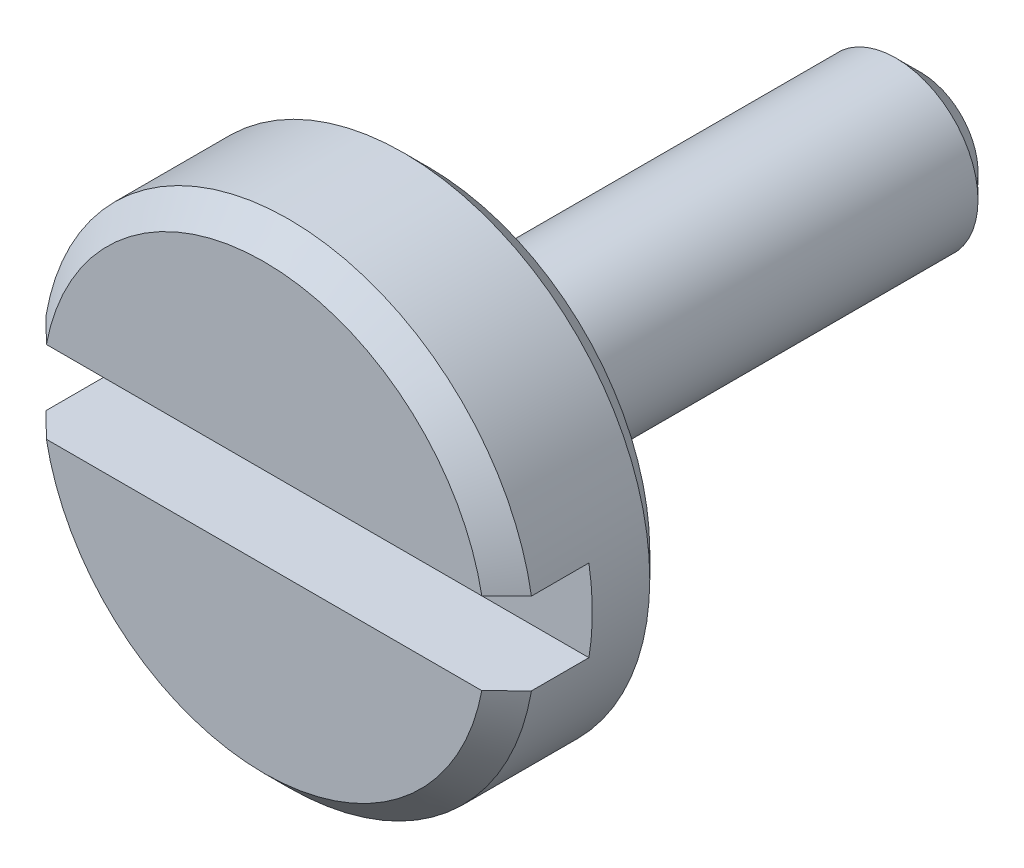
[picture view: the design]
ISO-10303-21;
HEADER;
FILE_DESCRIPTION(('STEP AP214'),'2;1');
FILE_NAME('part.step','',(''),(''),'','','');
FILE_SCHEMA(('AUTOMOTIVE_DESIGN { 1 0 10303 214 1 1 1 1 }'));
ENDSEC;
DATA;
#1=APPLICATION_CONTEXT('core data for automotive mechanical design processes');
#2=APPLICATION_PROTOCOL_DEFINITION('international standard','automotive_design',2000,#1);
#3=PRODUCT_CONTEXT('',#1,'mechanical');
#4=PRODUCT('Part','Part','',(#3));
#5=PRODUCT_RELATED_PRODUCT_CATEGORY('part','',(#4));
#6=PRODUCT_DEFINITION_FORMATION('','',#4);
#7=PRODUCT_DEFINITION_CONTEXT('part definition',#1,'design');
#8=PRODUCT_DEFINITION('design','',#6,#7);
#9=PRODUCT_DEFINITION_SHAPE('','',#8);
#10=(LENGTH_UNIT() NAMED_UNIT(*) SI_UNIT(.MILLI.,.METRE.));
#11=(NAMED_UNIT(*) PLANE_ANGLE_UNIT() SI_UNIT($,.RADIAN.));
#12=(NAMED_UNIT(*) SI_UNIT($,.STERADIAN.) SOLID_ANGLE_UNIT());
#13=UNCERTAINTY_MEASURE_WITH_UNIT(LENGTH_MEASURE(1.E-05),#10,'distance_accuracy_value','');
#14=(GEOMETRIC_REPRESENTATION_CONTEXT(3) GLOBAL_UNCERTAINTY_ASSIGNED_CONTEXT((#13)) GLOBAL_UNIT_ASSIGNED_CONTEXT((#10,
#11,#12)) REPRESENTATION_CONTEXT('',''));
#15=CARTESIAN_POINT('',(0.,0.,0.));
#16=DIRECTION('',(0.,0.,1.));
#17=DIRECTION('',(1.,0.,0.));
#18=AXIS2_PLACEMENT_3D('',#15,#16,#17);
#19=CARTESIAN_POINT('',(0.,0.,-60.));
#20=DIRECTION('',(0.,0.,-1.));
#21=DIRECTION('',(-1.,0.,0.));
#22=AXIS2_PLACEMENT_3D('',#19,#20,#21);
#23=PLANE('',#22);
#24=CARTESIAN_POINT('',(0.,0.,-60.));
#25=DIRECTION('',(0.,0.,-1.));
#26=DIRECTION('',(-1.,0.,0.));
#27=AXIS2_PLACEMENT_3D('',#24,#25,#26);
#28=CIRCLE('',#27,7.00000000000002);
#29=CARTESIAN_POINT('',(-7.00000000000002,0.,-60.));
#30=VERTEX_POINT('',#29);
#31=EDGE_CURVE('E345',#30,#30,#28,.T.);
#32=ORIENTED_EDGE('',*,*,#31,.T.);
#33=EDGE_LOOP('',(#32));
#34=FACE_BOUND('',#33,.T.);
#35=CARTESIAN_POINT('',(-0.572517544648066,-0.773288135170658,-60.));
#36=CARTESIAN_POINT('',(-0.571860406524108,-0.804666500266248,-60.));
#37=CARTESIAN_POINT('',(-0.570558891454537,-0.866813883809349,-60.));
#38=CARTESIAN_POINT('',(-0.555597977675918,-0.95806896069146,-60.));
#39=CARTESIAN_POINT('',(-0.533678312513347,-1.04669983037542,-60.));
#40=CARTESIAN_POINT('',(-0.500641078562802,-1.13161094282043,-60.));
#41=CARTESIAN_POINT('',(-0.460317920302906,-1.21435570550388,-60.));
#42=CARTESIAN_POINT('',(-0.409151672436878,-1.2927636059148,-60.));
#43=CARTESIAN_POINT('',(-0.349843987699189,-1.36857000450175,-60.));
#44=CARTESIAN_POINT('',(-0.281810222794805,-1.43975349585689,-60.));
#45=CARTESIAN_POINT('',(-0.207364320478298,-1.5050996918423,-60.));
#46=CARTESIAN_POINT('',(-0.128680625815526,-1.56322875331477,-60.));
#47=CARTESIAN_POINT('',(-0.0456303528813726,-1.61169707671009,-60.));
#48=CARTESIAN_POINT('',(0.0413359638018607,-1.65124791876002,-60.));
#49=CARTESIAN_POINT('',(0.132238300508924,-1.68218143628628,-60.));
#50=CARTESIAN_POINT('',(0.227046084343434,-1.70459430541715,-60.));
#51=CARTESIAN_POINT('',(0.325915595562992,-1.71835001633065,-60.));
#52=CARTESIAN_POINT('',(0.393116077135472,-1.71977777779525,-60.));
#53=CARTESIAN_POINT('',(0.427282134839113,-1.72050368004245,-60.));
#54=B_SPLINE_CURVE_WITH_KNOTS('',3,(#35,#36,#37,#38,#39,#40,#41,#42,#43,#44,#45,#46,#47,#48,#49,
#50,#51,#52,#53),.UNSPECIFIED.,.F.,.F.,(4,1,1,1,1,1,1,1,1,1,1,1,1,1,1,1,4),(0.,
0.0614842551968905,0.12177452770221,0.180919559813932,0.240256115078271,0.300114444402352,
0.361145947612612,0.423500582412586,0.488669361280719,0.553954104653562,0.617581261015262,
0.68023842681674,0.742187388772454,0.804663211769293,0.868258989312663,0.933020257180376,1.),.UNSPECIFIED.);
#55=CARTESIAN_POINT('',(-0.572517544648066,-0.773288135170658,-60.));
#56=VERTEX_POINT('',#55);
#57=CARTESIAN_POINT('',(0.427282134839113,-1.72050368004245,-60.));
#58=VERTEX_POINT('',#57);
#59=EDGE_CURVE('E216',#56,#58,#54,.T.);
#60=ORIENTED_EDGE('',*,*,#59,.T.);
#61=CARTESIAN_POINT('',(0.427282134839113,-1.72050368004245,-60.));
#62=CARTESIAN_POINT('',(0.453717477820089,-1.71999249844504,-60.));
#63=CARTESIAN_POINT('',(0.506255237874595,-1.71897657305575,-60.));
#64=CARTESIAN_POINT('',(0.583964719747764,-1.70999529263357,-60.));
#65=CARTESIAN_POINT('',(0.660104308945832,-1.69728818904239,-60.));
#66=CARTESIAN_POINT('',(0.733718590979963,-1.67711411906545,-60.));
#67=CARTESIAN_POINT('',(0.805756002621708,-1.65263714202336,-60.));
#68=CARTESIAN_POINT('',(0.875903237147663,-1.62249880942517,-60.));
#69=CARTESIAN_POINT('',(0.944194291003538,-1.5863816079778,-60.));
#70=CARTESIAN_POINT('',(1.01101187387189,-1.54508658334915,-60.));
#71=CARTESIAN_POINT('',(1.07618604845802,-1.49702883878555,-60.));
#72=CARTESIAN_POINT('',(1.13910551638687,-1.44105534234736,-60.));
#73=CARTESIAN_POINT('',(1.20183470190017,-1.37870983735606,-60.));
#74=CARTESIAN_POINT('',(1.26252209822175,-1.30829927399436,-60.));
#75=CARTESIAN_POINT('',(1.32239524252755,-1.23096119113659,-60.));
#76=CARTESIAN_POINT('',(1.38027365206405,-1.14597200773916,-60.));
#77=CARTESIAN_POINT('',(1.43735536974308,-1.05379465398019,-60.));
#78=CARTESIAN_POINT('',(1.47317083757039,-0.98892956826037,-60.));
#79=CARTESIAN_POINT('',(1.4915850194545,-0.955579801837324,-60.));
#80=B_SPLINE_CURVE_WITH_KNOTS('',3,(#61,#62,#63,#64,#65,#66,#67,#68,#69,#70,#71,#72,#73,#74,#75,
#76,#77,#78,#79),.UNSPECIFIED.,.F.,.F.,(4,1,1,1,1,1,1,1,1,1,1,1,1,1,1,1,4),(0.,
0.0572082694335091,0.11369605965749,0.169177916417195,0.224159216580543,0.278719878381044,
0.333794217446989,0.389241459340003,0.445822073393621,0.50370428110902,0.564293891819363,
0.627975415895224,0.695038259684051,0.765372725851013,0.839611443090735,0.917537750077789,1.),.UNSPECIFIED.);
#81=CARTESIAN_POINT('',(1.4915850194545,-0.955579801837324,-60.));
#82=VERTEX_POINT('',#81);
#83=EDGE_CURVE('E49',#58,#82,#80,.T.);
#84=ORIENTED_EDGE('',*,*,#83,.T.);
#85=DIRECTION('',(-0.857672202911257,0.514196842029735,0.));
#86=VECTOR('',#85,1.);
#87=CARTESIAN_POINT('',(1.4915850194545,-0.955579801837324,-60.));
#88=LINE('',#87,#86);
#89=CARTESIAN_POINT('',(1.1957116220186,-0.77819598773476,-60.));
#90=VERTEX_POINT('',#89);
#91=EDGE_CURVE('E220',#82,#90,#88,.T.);
#92=ORIENTED_EDGE('',*,*,#91,.T.);
#93=CARTESIAN_POINT('',(1.1957116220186,-0.77819598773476,-60.));
#94=CARTESIAN_POINT('',(1.16819338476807,-0.824260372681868,-60.));
#95=CARTESIAN_POINT('',(1.11546950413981,-0.912517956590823,-60.));
#96=CARTESIAN_POINT('',(1.02751814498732,-1.0317759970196,-60.));
#97=CARTESIAN_POINT('',(0.9363852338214,-1.13313815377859,-60.));
#98=CARTESIAN_POINT('',(0.841395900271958,-1.21601476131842,-60.));
#99=CARTESIAN_POINT('',(0.743129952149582,-1.28126364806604,-60.));
#100=CARTESIAN_POINT('',(0.640945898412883,-1.32746587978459,-60.));
#101=CARTESIAN_POINT('',(0.535188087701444,-1.35628185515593,-60.));
#102=CARTESIAN_POINT('',(0.463214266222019,-1.35978194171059,-60.));
#103=CARTESIAN_POINT('',(0.427282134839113,-1.36152932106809,-60.));
#104=B_SPLINE_CURVE_WITH_KNOTS('',3,(#93,#94,#95,#96,#97,#98,#99,#100,#101,#102,#103),
.UNSPECIFIED.,.F.,.F.,(4,1,1,1,1,1,1,1,4),(0.,0.159004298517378,0.304646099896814,
0.438546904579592,0.562322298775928,0.677432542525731,0.786897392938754,0.893610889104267,1.),.UNSPECIFIED.);
#105=CARTESIAN_POINT('',(0.427282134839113,-1.36152932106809,-60.));
#106=VERTEX_POINT('',#105);
#107=EDGE_CURVE('E673',#90,#106,#104,.T.);
#108=ORIENTED_EDGE('',*,*,#107,.T.);
#109=CARTESIAN_POINT('',(0.427282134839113,-1.36152932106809,-60.));
#110=CARTESIAN_POINT('',(0.39659527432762,-1.36067464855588,-60.));
#111=CARTESIAN_POINT('',(0.335758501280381,-1.35898025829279,-60.));
#112=CARTESIAN_POINT('',(0.246196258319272,-1.34269945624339,-60.));
#113=CARTESIAN_POINT('',(0.159214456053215,-1.31768732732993,-60.));
#114=CARTESIAN_POINT('',(0.0766058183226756,-1.28186639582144,-60.));
#115=CARTESIAN_POINT('',(-0.000489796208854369,-1.23852791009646,-60.));
#116=CARTESIAN_POINT('',(-0.0680964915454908,-1.18618173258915,-60.));
#117=CARTESIAN_POINT('',(-0.126542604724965,-1.12757552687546,-60.));
#118=CARTESIAN_POINT('',(-0.174351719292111,-1.06219287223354,-60.));
#119=CARTESIAN_POINT('',(-0.211031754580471,-0.991875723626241,-60.));
#120=CARTESIAN_POINT('',(-0.239223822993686,-0.919699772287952,-60.));
#121=CARTESIAN_POINT('',(-0.25486889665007,-0.844531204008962,-60.));
#122=CARTESIAN_POINT('',(-0.257225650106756,-0.793920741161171,-60.));
#123=CARTESIAN_POINT('',(-0.258414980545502,-0.768380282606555,-60.));
#124=B_SPLINE_CURVE_WITH_KNOTS('',3,(#109,#110,#111,#112,#113,#114,#115,#116,#117,#118,#119,
#120,#121,#122,#123),.UNSPECIFIED.,.F.,.F.,(4,1,1,1,1,1,1,1,1,1,1,1,4),(0.,0.0912636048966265,
0.180930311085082,0.270088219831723,0.360156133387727,0.448342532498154,0.53266584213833,
0.613833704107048,0.693981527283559,0.772715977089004,0.849335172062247,0.923967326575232,1.),.UNSPECIFIED.);
#125=CARTESIAN_POINT('',(-0.258414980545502,-0.768380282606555,-60.));
#126=VERTEX_POINT('',#125);
#127=EDGE_CURVE('E678',#106,#126,#124,.T.);
#128=ORIENTED_EDGE('',*,*,#127,.T.);
#129=CARTESIAN_POINT('',(-0.258414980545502,-0.768380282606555,-60.));
#130=CARTESIAN_POINT('',(-0.256940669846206,-0.739239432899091,-60.));
#131=CARTESIAN_POINT('',(-0.253943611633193,-0.680000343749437,-60.));
#132=CARTESIAN_POINT('',(-0.228612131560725,-0.592600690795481,-60.));
#133=CARTESIAN_POINT('',(-0.188762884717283,-0.506108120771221,-60.));
#134=CARTESIAN_POINT('',(-0.152000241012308,-0.45260685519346,-60.));
#135=CARTESIAN_POINT('',(-0.132914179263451,-0.424830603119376,-60.));
#136=B_SPLINE_CURVE_WITH_KNOTS('',3,(#129,#130,#131,#132,#133,#134,#135),.UNSPECIFIED.,.F.,.F.,
(4,1,1,1,4),(0.,0.234723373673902,0.477158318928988,0.728556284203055,1.),.UNSPECIFIED.);
#137=CARTESIAN_POINT('',(-0.132914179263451,-0.424830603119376,-60.));
#138=VERTEX_POINT('',#137);
#139=EDGE_CURVE('E686',#126,#138,#136,.T.);
#140=ORIENTED_EDGE('',*,*,#139,.T.);
#141=CARTESIAN_POINT('',(-0.132914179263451,-0.424830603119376,-60.));
#142=CARTESIAN_POINT('',(-0.117243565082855,-0.404783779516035,-60.));
#143=CARTESIAN_POINT('',(-0.0843450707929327,-0.36269798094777,-60.));
#144=CARTESIAN_POINT('',(-0.0277875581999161,-0.300052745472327,-60.));
#145=CARTESIAN_POINT('',(0.0385785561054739,-0.235434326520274,-60.));
#146=CARTESIAN_POINT('',(0.112482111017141,-0.166375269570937,-60.));
#147=CARTESIAN_POINT('',(0.196615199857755,-0.0960874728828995,-60.));
#148=CARTESIAN_POINT('',(0.288342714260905,-0.0212191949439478,-60.));
#149=CARTESIAN_POINT('',(0.390006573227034,0.0553823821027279,-60.));
#150=CARTESIAN_POINT('',(0.461306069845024,0.106754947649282,-60.));
#151=CARTESIAN_POINT('',(0.498095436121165,0.133262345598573,-60.));
#152=B_SPLINE_CURVE_WITH_KNOTS('',3,(#141,#142,#143,#144,#145,#146,#147,#148,#149,#150,#151),
.UNSPECIFIED.,.F.,.F.,(4,1,1,1,1,1,1,1,4),(0.,0.0902792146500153,0.189529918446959,
0.299197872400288,0.418925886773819,0.548376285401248,0.688136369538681,0.83908350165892,1.),.UNSPECIFIED.);
#153=CARTESIAN_POINT('',(0.498095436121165,0.133262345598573,-60.));
#154=VERTEX_POINT('',#153);
#155=EDGE_CURVE('E694',#138,#154,#152,.T.);
#156=ORIENTED_EDGE('',*,*,#155,.T.);
#157=CARTESIAN_POINT('',(0.498095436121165,0.133262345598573,-60.));
#158=CARTESIAN_POINT('',(0.534919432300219,0.1594909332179,-60.));
#159=CARTESIAN_POINT('',(0.605324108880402,0.209637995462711,-60.));
#160=CARTESIAN_POINT('',(0.703782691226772,0.284062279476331,-60.));
#161=CARTESIAN_POINT('',(0.791827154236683,0.352106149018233,-60.));
#162=CARTESIAN_POINT('',(0.869066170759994,0.414410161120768,-60.));
#163=CARTESIAN_POINT('',(0.935465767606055,0.470982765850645,-60.));
#164=CARTESIAN_POINT('',(0.9915491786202,0.521280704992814,-60.));
#165=CARTESIAN_POINT('',(1.03588773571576,0.566664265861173,-60.));
#166=CARTESIAN_POINT('',(1.06054331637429,0.596105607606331,-60.));
#167=CARTESIAN_POINT('',(1.07161306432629,0.609324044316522,-60.));
#168=B_SPLINE_CURVE_WITH_KNOTS('',3,(#157,#158,#159,#160,#161,#162,#163,#164,#165,#166,#167),
.UNSPECIFIED.,.F.,.F.,(4,1,1,1,1,1,1,1,4),(0.,0.181535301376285,0.347081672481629,
0.495567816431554,0.628357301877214,0.745519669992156,0.845830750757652,0.930781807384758,1.),.UNSPECIFIED.);
#169=CARTESIAN_POINT('',(1.07161306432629,0.609324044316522,-60.));
#170=VERTEX_POINT('',#169);
#171=EDGE_CURVE('E702',#154,#170,#168,.T.);
#172=ORIENTED_EDGE('',*,*,#171,.T.);
#173=CARTESIAN_POINT('',(1.07161306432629,0.609324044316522,-60.));
#174=CARTESIAN_POINT('',(1.08708560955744,0.629925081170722,-60.));
#175=CARTESIAN_POINT('',(1.11751444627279,0.670439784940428,-60.));
#176=CARTESIAN_POINT('',(1.15768045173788,0.733764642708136,-60.));
#177=CARTESIAN_POINT('',(1.19181961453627,0.798587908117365,-60.));
#178=CARTESIAN_POINT('',(1.21858194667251,0.865083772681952,-60.));
#179=CARTESIAN_POINT('',(1.24111816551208,0.932318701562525,-60.));
#180=CARTESIAN_POINT('',(1.25627609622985,1.00116994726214,-60.));
#181=CARTESIAN_POINT('',(1.26576749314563,1.07132856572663,-60.));
#182=CARTESIAN_POINT('',(1.26673947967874,1.11854206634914,-60.));
#183=CARTESIAN_POINT('',(1.26722604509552,1.14217660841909,-60.));
#184=B_SPLINE_CURVE_WITH_KNOTS('',3,(#173,#174,#175,#176,#177,#178,#179,#180,#181,#182,#183),
.UNSPECIFIED.,.F.,.F.,(4,1,1,1,1,1,1,1,4),(0.,0.133506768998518,0.26255897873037,
0.388264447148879,0.512667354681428,0.63372226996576,0.755393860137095,0.877552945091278,1.),.UNSPECIFIED.);
#185=CARTESIAN_POINT('',(1.26722604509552,1.14217660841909,-60.));
#186=VERTEX_POINT('',#185);
#187=EDGE_CURVE('E710',#170,#186,#184,.T.);
#188=ORIENTED_EDGE('',*,*,#187,.T.);
#189=CARTESIAN_POINT('',(1.26722604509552,1.14217660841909,-60.));
#190=CARTESIAN_POINT('',(1.26592083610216,1.17920638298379,-60.));
#191=CARTESIAN_POINT('',(1.26333831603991,1.25247444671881,-60.));
#192=CARTESIAN_POINT('',(1.2414977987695,1.35950527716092,-60.));
#193=CARTESIAN_POINT('',(1.20702490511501,1.46169169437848,-60.));
#194=CARTESIAN_POINT('',(1.15873001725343,1.5580220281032,-60.));
#195=CARTESIAN_POINT('',(1.0964726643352,1.64598800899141,-60.));
#196=CARTESIAN_POINT('',(1.02442668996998,1.72660149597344,-60.));
#197=CARTESIAN_POINT('',(0.938615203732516,1.79437007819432,-60.));
#198=CARTESIAN_POINT('',(0.844462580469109,1.85358213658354,-60.));
#199=CARTESIAN_POINT('',(0.741406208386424,1.89992806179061,-60.));
#200=CARTESIAN_POINT('',(0.633415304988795,1.9348890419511,-60.));
#201=CARTESIAN_POINT('',(0.520318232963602,1.95469829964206,-60.));
#202=CARTESIAN_POINT('',(0.443715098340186,1.9575410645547,-60.));
#203=CARTESIAN_POINT('',(0.404846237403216,1.95898349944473,-60.));
#204=B_SPLINE_CURVE_WITH_KNOTS('',3,(#189,#190,#191,#192,#193,#194,#195,#196,#197,#198,#199,
#200,#201,#202,#203),.UNSPECIFIED.,.F.,.F.,(4,1,1,1,1,1,1,1,1,1,1,1,4),(0.,0.0837853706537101,
0.165779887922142,0.246280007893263,0.32746092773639,0.408796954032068,0.489715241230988,
0.571376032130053,0.655523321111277,0.741019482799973,0.826546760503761,0.911988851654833,1.),.UNSPECIFIED.);
#205=CARTESIAN_POINT('',(0.404846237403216,1.95898349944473,-60.));
#206=VERTEX_POINT('',#205);
#207=EDGE_CURVE('E718',#186,#206,#204,.T.);
#208=ORIENTED_EDGE('',*,*,#207,.T.);
#209=CARTESIAN_POINT('',(0.404846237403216,1.95898349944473,-60.));
#210=CARTESIAN_POINT('',(0.363602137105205,1.95756094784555,-60.));
#211=CARTESIAN_POINT('',(0.281580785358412,1.95473194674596,-60.));
#212=CARTESIAN_POINT('',(0.160931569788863,1.93013441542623,-60.));
#213=CARTESIAN_POINT('',(0.0447708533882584,1.88943374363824,-60.));
#214=CARTESIAN_POINT('',(-0.048672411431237,1.84324508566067,-60.));
#215=CARTESIAN_POINT('',(-0.121805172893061,1.7971136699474,-60.));
#216=CARTESIAN_POINT('',(-0.177577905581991,1.75509384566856,-60.));
#217=CARTESIAN_POINT('',(-0.234095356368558,1.70671873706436,-60.));
#218=CARTESIAN_POINT('',(-0.291813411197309,1.65185949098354,-60.));
#219=CARTESIAN_POINT('',(-0.349754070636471,1.59001273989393,-60.));
#220=CARTESIAN_POINT('',(-0.408777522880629,1.52160205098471,-60.));
#221=CARTESIAN_POINT('',(-0.46902179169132,1.44704549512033,-60.));
#222=CARTESIAN_POINT('',(-0.507777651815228,1.39382099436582,-60.));
#223=CARTESIAN_POINT('',(-0.527645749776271,1.36653558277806,-60.));
#224=B_SPLINE_CURVE_WITH_KNOTS('',3,(#209,#210,#211,#212,#213,#214,#215,#216,#217,#218,#219,
#220,#221,#222,#223),.UNSPECIFIED.,.F.,.F.,(4,1,1,1,1,1,1,1,1,1,1,1,4),(0.,0.107232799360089,
0.213251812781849,0.318830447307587,0.426793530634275,0.483645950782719,0.543603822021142,
0.608307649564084,0.677126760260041,0.750685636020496,0.828713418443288,0.912190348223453,1.),.UNSPECIFIED.);
#225=CARTESIAN_POINT('',(-0.527645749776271,1.36653558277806,-60.));
#226=VERTEX_POINT('',#225);
#227=EDGE_CURVE('E726',#206,#226,#224,.T.);
#228=ORIENTED_EDGE('',*,*,#227,.T.);
#229=DIRECTION('',(0.796919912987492,-0.604084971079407,0.));
#230=VECTOR('',#229,1.);
#231=CARTESIAN_POINT('',(-0.527645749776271,1.36653558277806,-60.));
#232=LINE('',#231,#230);
#233=CARTESIAN_POINT('',(-0.243691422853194,1.15129119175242,-60.));
#234=VERTEX_POINT('',#233);
#235=EDGE_CURVE('E734',#226,#234,#232,.T.);
#236=ORIENTED_EDGE('',*,*,#235,.T.);
#237=CARTESIAN_POINT('',(-0.243691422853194,1.15129119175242,-60.));
#238=CARTESIAN_POINT('',(-0.226545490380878,1.17337988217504,-60.));
#239=CARTESIAN_POINT('',(-0.193526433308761,1.21591753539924,-60.));
#240=CARTESIAN_POINT('',(-0.143396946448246,1.2754888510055,-60.));
#241=CARTESIAN_POINT('',(-0.0961482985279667,1.32990533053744,-60.));
#242=CARTESIAN_POINT('',(-0.049597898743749,1.37717045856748,-60.));
#243=CARTESIAN_POINT('',(-0.00620426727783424,1.41987259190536,-60.));
#244=CARTESIAN_POINT('',(0.0359127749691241,1.45643234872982,-60.));
#245=CARTESIAN_POINT('',(0.0761471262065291,1.48720794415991,-60.));
#246=CARTESIAN_POINT('',(0.126864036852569,1.52005150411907,-60.));
#247=CARTESIAN_POINT('',(0.190581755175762,1.55260800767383,-60.));
#248=CARTESIAN_POINT('',(0.27056629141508,1.58015708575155,-60.));
#249=CARTESIAN_POINT('',(0.354152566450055,1.59671214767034,-60.));
#250=CARTESIAN_POINT('',(0.411082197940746,1.59890103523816,-60.));
#251=CARTESIAN_POINT('',(0.439902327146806,1.60000914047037,-60.));
#252=B_SPLINE_CURVE_WITH_KNOTS('',3,(#237,#238,#239,#240,#241,#242,#243,#244,#245,#246,#247,
#248,#249,#250,#251),.UNSPECIFIED.,.F.,.F.,(4,1,1,1,1,1,1,1,1,1,1,1,4),(0.,0.0984694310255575,
0.189629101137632,0.27418408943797,0.352183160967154,0.42319887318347,0.488550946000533,
0.548473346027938,0.601440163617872,0.701198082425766,0.799591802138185,0.898545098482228,1.),.UNSPECIFIED.);
#253=CARTESIAN_POINT('',(0.439902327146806,1.60000914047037,-60.));
#254=VERTEX_POINT('',#253);
#255=EDGE_CURVE('E740',#234,#254,#252,.T.);
#256=ORIENTED_EDGE('',*,*,#255,.T.);
#257=CARTESIAN_POINT('',(0.439902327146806,1.60000914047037,-60.));
#258=CARTESIAN_POINT('',(0.476058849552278,1.59879744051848,-60.));
#259=CARTESIAN_POINT('',(0.545783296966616,1.59646079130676,-60.));
#260=CARTESIAN_POINT('',(0.644773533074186,1.57094080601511,-60.));
#261=CARTESIAN_POINT('',(0.733867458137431,1.53075894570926,-60.));
#262=CARTESIAN_POINT('',(0.810420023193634,1.47444396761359,-60.));
#263=CARTESIAN_POINT('',(0.874157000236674,1.40772297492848,-60.));
#264=CARTESIAN_POINT('',(0.920262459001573,1.33094411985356,-60.));
#265=CARTESIAN_POINT('',(0.94801262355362,1.24616171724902,-60.));
#266=CARTESIAN_POINT('',(0.951398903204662,1.18702006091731,-60.));
#267=CARTESIAN_POINT('',(0.95312348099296,1.15690016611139,-60.));
#268=B_SPLINE_CURVE_WITH_KNOTS('',3,(#257,#258,#259,#260,#261,#262,#263,#264,#265,#266,#267),
.UNSPECIFIED.,.F.,.F.,(4,1,1,1,1,1,1,1,4),(0.,0.143073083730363,0.27590296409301,
0.402370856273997,0.528413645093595,0.650356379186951,0.765895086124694,0.880774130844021,1.),.UNSPECIFIED.);
#269=CARTESIAN_POINT('',(0.95312348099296,1.15690016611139,-60.));
#270=VERTEX_POINT('',#269);
#271=EDGE_CURVE('E745',#254,#270,#268,.T.);
#272=ORIENTED_EDGE('',*,*,#271,.T.);
#273=CARTESIAN_POINT('',(0.95312348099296,1.15690016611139,-60.));
#274=CARTESIAN_POINT('',(0.952730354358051,1.13814868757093,-60.));
#275=CARTESIAN_POINT('',(0.951943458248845,1.10061506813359,-60.));
#276=CARTESIAN_POINT('',(0.94096866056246,1.04516364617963,-60.));
#277=CARTESIAN_POINT('',(0.92686933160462,0.989852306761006,-60.));
#278=CARTESIAN_POINT('',(0.904526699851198,0.934929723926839,-60.));
#279=CARTESIAN_POINT('',(0.873681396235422,0.879435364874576,-60.));
#280=CARTESIAN_POINT('',(0.833176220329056,0.822413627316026,-60.));
#281=CARTESIAN_POINT('',(0.782162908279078,0.763361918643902,-60.));
#282=CARTESIAN_POINT('',(0.74308589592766,0.724954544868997,-60.));
#283=CARTESIAN_POINT('',(0.722454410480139,0.704676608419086,-60.));
#284=B_SPLINE_CURVE_WITH_KNOTS('',3,(#273,#274,#275,#276,#277,#278,#279,#280,#281,#282,#283),
.UNSPECIFIED.,.F.,.F.,(4,1,1,1,1,1,1,1,4),(0.,0.107285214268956,0.21474586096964,
0.322938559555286,0.434116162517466,0.553412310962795,0.68607298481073,0.834255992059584,1.),.UNSPECIFIED.);
#285=CARTESIAN_POINT('',(0.722454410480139,0.704676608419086,-60.));
#286=VERTEX_POINT('',#285);
#287=EDGE_CURVE('E753',#270,#286,#284,.T.);
#288=ORIENTED_EDGE('',*,*,#287,.T.);
#289=CARTESIAN_POINT('',(0.722454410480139,0.704676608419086,-60.));
#290=CARTESIAN_POINT('',(0.71479303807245,0.697839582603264,-60.));
#291=CARTESIAN_POINT('',(0.696591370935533,0.681596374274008,-60.));
#292=CARTESIAN_POINT('',(0.663315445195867,0.655004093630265,-60.));
#293=CARTESIAN_POINT('',(0.619372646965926,0.622201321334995,-60.));
#294=CARTESIAN_POINT('',(0.565910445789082,0.581614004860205,-60.));
#295=CARTESIAN_POINT('',(0.501943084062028,0.534532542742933,-60.));
#296=CARTESIAN_POINT('',(0.42746352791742,0.481558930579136,-60.));
#297=CARTESIAN_POINT('',(0.343301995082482,0.420973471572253,-60.));
#298=CARTESIAN_POINT('',(0.283580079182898,0.378615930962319,-60.));
#299=CARTESIAN_POINT('',(0.252001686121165,0.356219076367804,-60.));
#300=B_SPLINE_CURVE_WITH_KNOTS('',3,(#289,#290,#291,#292,#293,#294,#295,#296,#297,#298,#299),
.UNSPECIFIED.,.F.,.F.,(4,1,1,1,1,1,1,1,4),(0.,0.0525942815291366,0.124951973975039,
0.218093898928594,0.333502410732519,0.468789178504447,0.624937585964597,0.801683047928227,1.),.UNSPECIFIED.);
#301=CARTESIAN_POINT('',(0.252001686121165,0.356219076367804,-60.));
#302=VERTEX_POINT('',#301);
#303=EDGE_CURVE('E761',#286,#302,#300,.T.);
#304=ORIENTED_EDGE('',*,*,#303,.T.);
#305=CARTESIAN_POINT('',(0.252001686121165,0.356219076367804,-60.));
#306=CARTESIAN_POINT('',(0.21401577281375,0.328577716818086,-60.));
#307=CARTESIAN_POINT('',(0.140461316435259,0.275054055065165,-60.));
#308=CARTESIAN_POINT('',(0.0358037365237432,0.194638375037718,-60.));
#309=CARTESIAN_POINT('',(-0.0590900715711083,0.115990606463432,-60.));
#310=CARTESIAN_POINT('',(-0.144553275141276,0.039612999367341,-60.));
#311=CARTESIAN_POINT('',(-0.221430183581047,-0.0339150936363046,-60.));
#312=CARTESIAN_POINT('',(-0.288867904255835,-0.105478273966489,-60.));
#313=CARTESIAN_POINT('',(-0.347553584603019,-0.174563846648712,-60.));
#314=CARTESIAN_POINT('',(-0.41073280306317,-0.263136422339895,-60.));
#315=CARTESIAN_POINT('',(-0.475290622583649,-0.371917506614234,-60.));
#316=CARTESIAN_POINT('',(-0.530732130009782,-0.505195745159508,-60.));
#317=CARTESIAN_POINT('',(-0.565690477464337,-0.638992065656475,-60.));
#318=CARTESIAN_POINT('',(-0.570261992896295,-0.728918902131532,-60.));
#319=CARTESIAN_POINT('',(-0.572517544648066,-0.773288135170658,-60.));
#320=B_SPLINE_CURVE_WITH_KNOTS('',3,(#305,#306,#307,#308,#309,#310,#311,#312,#313,#314,#315,
#316,#317,#318,#319),.UNSPECIFIED.,.F.,.F.,(4,1,1,1,1,1,1,1,1,1,1,1,4),(0.,0.0969723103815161,
0.187773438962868,0.272396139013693,0.351320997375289,0.424334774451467,0.491908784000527,
0.554233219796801,0.611267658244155,0.716347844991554,0.814540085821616,0.908495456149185,1.),.UNSPECIFIED.);
#321=EDGE_CURVE('E769',#302,#56,#320,.T.);
#322=ORIENTED_EDGE('',*,*,#321,.T.);
#323=EDGE_LOOP('',(#60,#84,#92,#108,#128,#140,#156,#172,#188,#208,#228,#236,#256,#272,#288,#304,#322));
#324=FACE_BOUND('',#323,.T.);
#325=ADVANCED_FACE('F34',(#34,#324),#23,.T.);
#326=CARTESIAN_POINT('',(0.,0.,-60.));
#327=DIRECTION('',(0.,0.,1.));
#328=DIRECTION('',(1.,0.,0.));
#329=AXIS2_PLACEMENT_3D('',#326,#327,#328);
#330=CYLINDRICAL_SURFACE('',#329,10.);
#331=CARTESIAN_POINT('',(0.,0.,0.));
#332=DIRECTION('',(0.,0.,1.));
#333=DIRECTION('',(1.,0.,0.));
#334=AXIS2_PLACEMENT_3D('',#331,#332,#333);
#335=CIRCLE('',#334,10.);
#336=CARTESIAN_POINT('',(10.,0.,0.));
#337=VERTEX_POINT('',#336);
#338=EDGE_CURVE('E349',#337,#337,#335,.F.);
#339=ORIENTED_EDGE('',*,*,#338,.T.);
#340=EDGE_LOOP('',(#339));
#341=FACE_BOUND('',#340,.T.);
#342=CARTESIAN_POINT('',(0.,0.,-57.));
#343=DIRECTION('',(0.,0.,-1.));
#344=DIRECTION('',(-1.,0.,0.));
#345=AXIS2_PLACEMENT_3D('',#342,#343,#344);
#346=CIRCLE('',#345,10.);
#347=CARTESIAN_POINT('',(-10.,0.,-57.));
#348=VERTEX_POINT('',#347);
#349=EDGE_CURVE('E343',#348,#348,#346,.F.);
#350=ORIENTED_EDGE('',*,*,#349,.T.);
#351=EDGE_LOOP('',(#350));
#352=FACE_BOUND('',#351,.T.);
#353=DIRECTION('',(0.,0.,1.));
#354=VECTOR('',#353,1.);
#355=CARTESIAN_POINT('',(-9.92156741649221,-1.25,-60.));
#356=LINE('',#355,#354);
#357=CARTESIAN_POINT('',(-9.92156741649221,-1.25,-51.1866580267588));
#358=VERTEX_POINT('',#357);
#359=CARTESIAN_POINT('',(-9.92156741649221,-1.25,-37.0592673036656));
#360=VERTEX_POINT('',#359);
#361=EDGE_CURVE('E11',#358,#360,#356,.T.);
#362=ORIENTED_EDGE('',*,*,#361,.F.);
#363=CARTESIAN_POINT('',(-9.92156741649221,-1.25,-51.1866580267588));
#364=CARTESIAN_POINT('',(-9.93460745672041,-1.14651016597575,-51.1997216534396));
#365=CARTESIAN_POINT('',(-9.94604927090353,-1.04262221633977,-51.2111190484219));
#366=CARTESIAN_POINT('',(-9.96569126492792,-0.834233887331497,-51.2306135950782));
#367=CARTESIAN_POINT('',(-9.97389150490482,-0.729733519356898,-51.238710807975));
#368=CARTESIAN_POINT('',(-9.9934586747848,-0.417245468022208,-51.2579985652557));
#369=CARTESIAN_POINT('',(-10.,-0.208622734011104,-51.2643910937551));
#370=CARTESIAN_POINT('',(-10.,0.208622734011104,-51.2643910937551));
#371=CARTESIAN_POINT('',(-9.9934586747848,0.417245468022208,-51.2579985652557));
#372=CARTESIAN_POINT('',(-9.97389150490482,0.729733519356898,-51.238710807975));
#373=CARTESIAN_POINT('',(-9.96569126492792,0.834233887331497,-51.2306135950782));
#374=CARTESIAN_POINT('',(-9.94604927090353,1.04262221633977,-51.2111190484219));
#375=CARTESIAN_POINT('',(-9.93460745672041,1.14651016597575,-51.1997216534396));
#376=CARTESIAN_POINT('',(-9.92156741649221,1.25,-51.1866580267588));
#377=B_SPLINE_CURVE_WITH_KNOTS('',3,(#363,#364,#365,#366,#367,#368,#369,#370,#371,#372,#373,
#374,#375,#376),.UNSPECIFIED.,.F.,.F.,(4,2,2,2,2,2,4),(0.,0.315316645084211,0.630627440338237,
1.25624528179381,1.88186312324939,2.19717391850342,2.51249056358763),.UNSPECIFIED.);
#378=CARTESIAN_POINT('',(-9.92156741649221,1.25,-51.1866580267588));
#379=VERTEX_POINT('',#378);
#380=EDGE_CURVE('E42',#358,#379,#377,.T.);
#381=ORIENTED_EDGE('',*,*,#380,.T.);
#382=DIRECTION('',(0.,0.,1.));
#383=VECTOR('',#382,1.);
#384=CARTESIAN_POINT('',(-9.92156741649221,1.25,-60.));
#385=LINE('',#384,#383);
#386=CARTESIAN_POINT('',(-9.92156741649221,1.25,-37.0592673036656));
#387=VERTEX_POINT('',#386);
#388=EDGE_CURVE('E342',#379,#387,#385,.T.);
#389=ORIENTED_EDGE('',*,*,#388,.T.);
#390=CARTESIAN_POINT('',(-9.92156741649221,1.25,-37.0592673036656));
#391=CARTESIAN_POINT('',(-9.93460745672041,1.14651016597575,-37.0462036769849));
#392=CARTESIAN_POINT('',(-9.94604927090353,1.04262221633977,-37.0348062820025));
#393=CARTESIAN_POINT('',(-9.96569126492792,0.834233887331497,-37.0153117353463));
#394=CARTESIAN_POINT('',(-9.97389150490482,0.729733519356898,-37.0072145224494));
#395=CARTESIAN_POINT('',(-9.9934586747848,0.417245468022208,-36.9879267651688));
#396=CARTESIAN_POINT('',(-10.,0.208622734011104,-36.9815342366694));
#397=CARTESIAN_POINT('',(-10.,-0.208622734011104,-36.9815342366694));
#398=CARTESIAN_POINT('',(-9.9934586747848,-0.417245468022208,-36.9879267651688));
#399=CARTESIAN_POINT('',(-9.97389150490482,-0.729733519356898,-37.0072145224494));
#400=CARTESIAN_POINT('',(-9.96569126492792,-0.834233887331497,-37.0153117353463));
#401=CARTESIAN_POINT('',(-9.94604927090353,-1.04262221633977,-37.0348062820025));
#402=CARTESIAN_POINT('',(-9.93460745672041,-1.14651016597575,-37.0462036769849));
#403=CARTESIAN_POINT('',(-9.92156741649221,-1.25,-37.0592673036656));
#404=B_SPLINE_CURVE_WITH_KNOTS('',3,(#390,#391,#392,#393,#394,#395,#396,#397,#398,#399,#400,
#401,#402,#403),.UNSPECIFIED.,.F.,.F.,(4,2,2,2,2,2,4),(0.,0.315316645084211,0.630627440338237,
1.25624528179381,1.88186312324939,2.19717391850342,2.51249056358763),.UNSPECIFIED.);
#405=EDGE_CURVE('E329',#387,#360,#404,.T.);
#406=ORIENTED_EDGE('',*,*,#405,.T.);
#407=EDGE_LOOP('',(#362,#381,#389,#406));
#408=FACE_BOUND('',#407,.T.);
#409=ADVANCED_FACE('F300',(#341,#352,#408),#330,.T.);
#410=CARTESIAN_POINT('',(0.,0.,0.));
#411=DIRECTION('',(0.,0.,1.));
#412=DIRECTION('',(1.,0.,0.));
#413=AXIS2_PLACEMENT_3D('',#410,#411,#412);
#414=PLANE('',#413);
#415=CARTESIAN_POINT('',(0.,0.,0.));
#416=DIRECTION('',(0.,0.,1.));
#417=DIRECTION('',(1.,0.,0.));
#418=AXIS2_PLACEMENT_3D('',#415,#416,#417);
#419=CIRCLE('',#418,27.);
#420=CARTESIAN_POINT('',(27.,0.,0.));
#421=VERTEX_POINT('',#420);
#422=EDGE_CURVE('E264',#421,#421,#419,.F.);
#423=ORIENTED_EDGE('',*,*,#422,.T.);
#424=EDGE_LOOP('',(#423));
#425=FACE_BOUND('',#424,.T.);
#426=ORIENTED_EDGE('',*,*,#338,.F.);
#427=EDGE_LOOP('',(#426));
#428=FACE_BOUND('',#427,.T.);
#429=ADVANCED_FACE('F298',(#425,#428),#414,.F.);
#430=CARTESIAN_POINT('',(0.,0.,20.));
#431=DIRECTION('',(0.,0.,1.));
#432=DIRECTION('',(1.,0.,0.));
#433=AXIS2_PLACEMENT_3D('',#430,#431,#432);
#434=PLANE('',#433);
#435=DIRECTION('',(-1.,0.,0.));
#436=VECTOR('',#435,1.);
#437=CARTESIAN_POINT('',(-31.8396190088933,5.,20.));
#438=LINE('',#437,#436);
#439=CARTESIAN_POINT('',(26.5329983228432,5.,20.));
#440=VERTEX_POINT('',#439);
#441=CARTESIAN_POINT('',(-26.5329983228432,5.,20.));
#442=VERTEX_POINT('',#441);
#443=EDGE_CURVE('E236',#440,#442,#438,.T.);
#444=ORIENTED_EDGE('',*,*,#443,.F.);
#445=CARTESIAN_POINT('',(0.,0.,20.));
#446=DIRECTION('',(0.,0.,1.));
#447=DIRECTION('',(1.,0.,0.));
#448=AXIS2_PLACEMENT_3D('',#445,#446,#447);
#449=CIRCLE('',#448,27.);
#450=EDGE_CURVE('E254',#440,#442,#449,.T.);
#451=ORIENTED_EDGE('',*,*,#450,.T.);
#452=EDGE_LOOP('',(#444,#451));
#453=FACE_BOUND('',#452,.T.);
#454=ADVANCED_FACE('F297',(#453),#434,.T.);
#455=CARTESIAN_POINT('',(0.,0.,20.));
#456=DIRECTION('',(0.,0.,-1.));
#457=DIRECTION('',(-1.,0.,0.));
#458=AXIS2_PLACEMENT_3D('',#455,#456,#457);
#459=CONICAL_SURFACE('',#458,27.,0.785398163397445);
#460=CARTESIAN_POINT('',(65.8556355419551,5.,-19.0451719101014));
#461=CARTESIAN_POINT('',(64.68929328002,5.,-17.8821787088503));
#462=CARTESIAN_POINT('',(63.5228644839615,5.,-16.7192722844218));
#463=CARTESIAN_POINT('',(61.1897976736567,5.,-14.393669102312));
#464=CARTESIAN_POINT('',(60.0231596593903,5.,-13.2309723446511));
#465=CARTESIAN_POINT('',(56.5227931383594,5.,-9.74316661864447));
#466=CARTESIAN_POINT('',(54.1886968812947,5.,-7.41842669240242));
#467=CARTESIAN_POINT('',(49.5170329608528,5.,-2.7683210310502));
#468=CARTESIAN_POINT('',(47.1794640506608,5.,-0.442956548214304));
#469=CARTESIAN_POINT('',(43.6715021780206,5.,3.04339004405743));
#470=CARTESIAN_POINT('',(42.5019339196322,5.,4.20520193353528));
#471=CARTESIAN_POINT('',(40.1620907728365,5.,6.52811218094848));
#472=CARTESIAN_POINT('',(38.9918158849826,5.,7.68921053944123));
#473=CARTESIAN_POINT('',(36.7013079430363,5.,9.95996136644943));
#474=CARTESIAN_POINT('',(35.5811139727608,5.,11.0696532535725));
#475=CARTESIAN_POINT('',(33.3396170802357,5.,13.2879231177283));
#476=CARTESIAN_POINT('',(32.2183141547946,5.,14.3965010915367));
#477=CARTESIAN_POINT('',(29.9740960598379,5.,16.6122623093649));
#478=CARTESIAN_POINT('',(28.851180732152,5.,17.7194453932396));
#479=CARTESIAN_POINT('',(26.6032702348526,5.,19.931675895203));
#480=CARTESIAN_POINT('',(25.4782750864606,5.,21.0367233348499));
#481=CARTESIAN_POINT('',(23.2258575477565,5.,23.2431345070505));
#482=CARTESIAN_POINT('',(22.0984367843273,5.,24.3444998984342));
#483=CARTESIAN_POINT('',(20.4037555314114,5.,25.9929457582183));
#484=CARTESIAN_POINT('',(19.8382583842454,5.,26.5418386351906));
#485=CARTESIAN_POINT('',(18.7057501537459,5.,27.6380584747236));
#486=CARTESIAN_POINT('',(18.1387390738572,5.,28.1853854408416));
#487=CARTESIAN_POINT('',(17.0028555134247,5.,29.2778978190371));
#488=CARTESIAN_POINT('',(16.4339833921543,5.,29.8230836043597));
#489=CARTESIAN_POINT('',(15.2936191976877,5.,30.9107058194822));
#490=CARTESIAN_POINT('',(14.7221271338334,5.,31.4531422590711));
#491=CARTESIAN_POINT('',(13.5755888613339,5.,32.5341815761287));
#492=CARTESIAN_POINT('',(13.0005428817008,5.,33.0727846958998));
#493=CARTESIAN_POINT('',(12.1341242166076,5.,33.8765296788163));
#494=CARTESIAN_POINT('',(11.8446789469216,5.,34.1437490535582));
#495=CARTESIAN_POINT('',(11.2642175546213,5.,34.6764753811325));
#496=CARTESIAN_POINT('',(10.973201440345,5.,34.9419823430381));
#497=CARTESIAN_POINT('',(10.5190691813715,5.,35.3532789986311));
#498=CARTESIAN_POINT('',(10.3566207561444,5.,35.4998061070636));
#499=CARTESIAN_POINT('',(10.0310484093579,5.,35.7921104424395));
#500=CARTESIAN_POINT('',(9.86792448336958,5.,35.937887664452));
#501=CARTESIAN_POINT('',(9.54089744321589,5.,36.2285975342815));
#502=CARTESIAN_POINT('',(9.37699425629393,5.,36.3735301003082));
#503=CARTESIAN_POINT('',(9.04831656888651,5.,36.6624035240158));
#504=CARTESIAN_POINT('',(8.88354206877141,5.,36.8063443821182));
#505=CARTESIAN_POINT('',(8.38538551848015,5.,37.2384859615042));
#506=CARTESIAN_POINT('',(8.05048455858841,5.,37.5249412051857));
#507=CARTESIAN_POINT('',(7.37540456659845,5.,38.091423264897));
#508=CARTESIAN_POINT('',(7.03522692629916,5.,38.3714517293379));
#509=CARTESIAN_POINT('',(6.51816738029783,5.,38.7856310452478));
#510=CARTESIAN_POINT('',(6.34403051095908,5.,38.9232073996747));
#511=CARTESIAN_POINT('',(5.99353583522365,5.,39.1954972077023));
#512=CARTESIAN_POINT('',(5.81717809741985,5.,39.3302107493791));
#513=CARTESIAN_POINT('',(5.46159323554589,5.,39.5962799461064));
#514=CARTESIAN_POINT('',(5.28236277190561,5.,39.7276311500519));
#515=CARTESIAN_POINT('',(4.92073426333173,5.,39.9859001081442));
#516=CARTESIAN_POINT('',(4.73833634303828,5.,40.1128180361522));
#517=CARTESIAN_POINT('',(4.37091006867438,5.,40.3602322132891));
#518=CARTESIAN_POINT('',(4.18590597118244,5.,40.4807643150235));
#519=CARTESIAN_POINT('',(3.81135724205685,5.,40.7146966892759));
#520=CARTESIAN_POINT('',(3.62181166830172,5.,40.8280954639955));
#521=CARTESIAN_POINT('',(3.23781372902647,5.,41.0453031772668));
#522=CARTESIAN_POINT('',(3.04337312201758,5.,41.149132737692));
#523=CARTESIAN_POINT('',(2.648453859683,5.,41.3444823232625));
#524=CARTESIAN_POINT('',(2.44797898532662,5.,41.4360098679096));
#525=CARTESIAN_POINT('',(2.09118241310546,5.,41.5821043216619));
#526=CARTESIAN_POINT('',(1.93631281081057,5.,41.6401970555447));
#527=CARTESIAN_POINT('',(1.62280468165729,5.,41.7453167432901));
#528=CARTESIAN_POINT('',(1.4641660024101,5.,41.7923432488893));
#529=CARTESIAN_POINT('',(1.14419944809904,5.,41.8730754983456));
#530=CARTESIAN_POINT('',(0.982885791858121,5.,41.9068367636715));
#531=CARTESIAN_POINT('',(0.657825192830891,5.,41.9594604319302));
#532=CARTESIAN_POINT('',(0.494078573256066,5.,41.978324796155));
#533=CARTESIAN_POINT('',(0.16391020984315,5.,42.0000512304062));
#534=CARTESIAN_POINT('',(-0.00252208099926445,5.,42.0027564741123));
#535=CARTESIAN_POINT('',(-0.334816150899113,5.,41.9915552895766));
#536=CARTESIAN_POINT('',(-0.500677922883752,5.,41.9776486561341));
#537=CARTESIAN_POINT('',(-0.830782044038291,5.,41.9341014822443));
#538=CARTESIAN_POINT('',(-0.99501820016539,5.,41.9044148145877));
#539=CARTESIAN_POINT('',(-1.32031294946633,5.,41.83104631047));
#540=CARTESIAN_POINT('',(-1.48137078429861,5.,41.7873611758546));
#541=CARTESIAN_POINT('',(-1.88086272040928,5.,41.662821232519));
#542=CARTESIAN_POINT('',(-2.11691618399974,5.,41.5743682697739));
#543=CARTESIAN_POINT('',(-2.58043788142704,5.,41.377322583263));
#544=CARTESIAN_POINT('',(-2.80789931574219,5.,41.2687142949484));
#545=CARTESIAN_POINT('',(-3.14380644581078,5.,41.094549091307));
#546=CARTESIAN_POINT('',(-3.25514910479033,5.,41.0344645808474));
#547=CARTESIAN_POINT('',(-3.47606041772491,5.,40.9111096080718));
#548=CARTESIAN_POINT('',(-3.58562905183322,5.,40.8478391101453));
#549=CARTESIAN_POINT('',(-3.80309504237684,5.,40.718607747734));
#550=CARTESIAN_POINT('',(-3.91099312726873,5.,40.6526481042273));
#551=CARTESIAN_POINT('',(-4.12531480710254,5.,40.5183907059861));
#552=CARTESIAN_POINT('',(-4.23173846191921,5.,40.4500930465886));
#553=CARTESIAN_POINT('',(-4.58975559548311,5.,40.2155017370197));
#554=CARTESIAN_POINT('',(-4.83826444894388,5.,40.0444941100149));
#555=CARTESIAN_POINT('',(-5.32945766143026,5.,39.6942796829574));
#556=CARTESIAN_POINT('',(-5.57214066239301,5.,39.515070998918));
#557=CARTESIAN_POINT('',(-6.0530876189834,5.,39.1504602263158));
#558=CARTESIAN_POINT('',(-6.29134803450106,5.,38.9650534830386));
#559=CARTESIAN_POINT('',(-6.76419305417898,5.,38.5896689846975));
#560=CARTESIAN_POINT('',(-6.99877797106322,5.,38.3996916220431));
#561=CARTESIAN_POINT('',(-7.46559346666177,5.,38.0157116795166));
#562=CARTESIAN_POINT('',(-7.697816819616,5.,37.8217003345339));
#563=CARTESIAN_POINT('',(-8.15988097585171,5.,37.4308577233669));
#564=CARTESIAN_POINT('',(-8.38972173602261,5.,37.234026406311));
#565=CARTESIAN_POINT('',(-8.84734688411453,5.,36.8381906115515));
#566=CARTESIAN_POINT('',(-9.07513212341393,5.,36.6391871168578));
#567=CARTESIAN_POINT('',(-9.52908055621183,5.,36.2393373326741));
#568=CARTESIAN_POINT('',(-9.75524373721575,5.,36.0384910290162));
#569=CARTESIAN_POINT('',(-10.4325949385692,5.,35.432897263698));
#570=CARTESIAN_POINT('',(-10.8817485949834,5.,35.025874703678));
#571=CARTESIAN_POINT('',(-11.776212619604,5.,34.2075509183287));
#572=CARTESIAN_POINT('',(-12.2215225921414,5.,33.7962492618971));
#573=CARTESIAN_POINT('',(-13.1085597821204,5.,32.971176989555));
#574=CARTESIAN_POINT('',(-13.5502914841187,5.,32.5574111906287));
#575=CARTESIAN_POINT('',(-14.4315399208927,5.,31.7275608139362));
#576=CARTESIAN_POINT('',(-14.8710567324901,5.,31.3114763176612));
#577=CARTESIAN_POINT('',(-15.7442912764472,5.,30.4813888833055));
#578=CARTESIAN_POINT('',(-16.1780248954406,5.,30.0674026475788));
#579=CARTESIAN_POINT('',(-17.0441516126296,5.,29.238029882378));
#580=CARTESIAN_POINT('',(-17.4765447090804,5.,28.8226433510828));
#581=CARTESIAN_POINT('',(-18.7721181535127,5.,27.5748071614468));
#582=CARTESIAN_POINT('',(-19.6336878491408,5.,26.7406854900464));
#583=CARTESIAN_POINT('',(-21.3539494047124,5.,25.0694293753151));
#584=CARTESIAN_POINT('',(-22.2126411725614,5.,24.2322948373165));
#585=CARTESIAN_POINT('',(-23.9279511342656,5.,22.5559030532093));
#586=CARTESIAN_POINT('',(-24.7845693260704,5.,21.7166458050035));
#587=CARTESIAN_POINT('',(-26.4968110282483,5.,20.036057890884));
#588=CARTESIAN_POINT('',(-27.352433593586,5.,19.1947262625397));
#589=CARTESIAN_POINT('',(-29.0625198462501,5.,17.5108850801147));
#590=CARTESIAN_POINT('',(-29.9169835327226,5.,16.6683755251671));
#591=CARTESIAN_POINT('',(-32.4790160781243,5.,14.1395254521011));
#592=CARTESIAN_POINT('',(-34.1852538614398,5.,12.4518365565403));
#593=CARTESIAN_POINT('',(-37.591392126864,5.,9.07825999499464));
#594=CARTESIAN_POINT('',(-39.2912979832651,5.,7.39237775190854));
#595=CARTESIAN_POINT('',(-42.6895996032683,5.,4.01907843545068));
#596=CARTESIAN_POINT('',(-44.387995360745,5.,2.3316613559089));
#597=CARTESIAN_POINT('',(-47.7834450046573,5.,-1.04398210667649));
#598=CARTESIAN_POINT('',(-49.480499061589,5.,-2.73220831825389));
#599=CARTESIAN_POINT('',(-52.8738193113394,5.,-6.10944904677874));
#600=CARTESIAN_POINT('',(-54.5700855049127,5.,-7.798463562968));
#601=CARTESIAN_POINT('',(-57.0650936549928,5.,-10.2836796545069));
#602=CARTESIAN_POINT('',(-57.8640668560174,5.,-11.0796491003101));
#603=CARTESIAN_POINT('',(-59.461916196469,5.,-12.6717258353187));
#604=CARTESIAN_POINT('',(-60.2607923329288,5.,-13.467833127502));
#605=CARTESIAN_POINT('',(-61.8590598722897,5.,-15.0607688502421));
#606=CARTESIAN_POINT('',(-62.6584511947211,5.,-15.857597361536));
#607=CARTESIAN_POINT('',(-64.2571205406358,5.,-17.4513274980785));
#608=CARTESIAN_POINT('',(-65.0563985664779,5.,-18.2482291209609));
#609=CARTESIAN_POINT('',(-65.8556355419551,5.,-19.0451719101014));
#610=B_SPLINE_CURVE_WITH_KNOTS('',3,(#460,#461,#462,#463,#464,#465,#466,#467,#468,#469,#470,
#471,#472,#473,#474,#475,#476,#477,#478,#479,#480,#481,#482,#483,#484,#485,#486,#487,#488,#489,
#490,#491,#492,#493,#494,#495,#496,#497,#498,#499,#500,#501,#502,#503,#504,#505,#506,#507,#508,
#509,#510,#511,#512,#513,#514,#515,#516,#517,#518,#519,#520,#521,#522,#523,#524,#525,#526,#527,
#528,#529,#530,#531,#532,#533,#534,#535,#536,#537,#538,#539,#540,#541,#542,#543,#544,#545,#546,
#547,#548,#549,#550,#551,#552,#553,#554,#555,#556,#557,#558,#559,#560,#561,#562,#563,#564,#565,
#566,#567,#568,#569,#570,#571,#572,#573,#574,#575,#576,#577,#578,#579,#580,#581,#582,#583,#584,
#585,#586,#587,#588,#589,#590,#591,#592,#593,#594,#595,#596,#597,#598,#599,#600,#601,#602,#603,
#604,#605,#606,#607,#608,#609),.UNSPECIFIED.,.F.,.F.,(4,2,2,2,2,2,2,2,2,2,2,2,2,2,2,2,2,2,2,2,2,
2,2,2,2,2,2,2,2,2,2,2,2,2,2,2,2,2,2,2,2,2,2,2,2,2,2,2,2,2,2,2,2,2,2,2,2,2,2,2,2,2,2,2,2,2,2,2,2,
2,2,2,2,2,4),(0.,4.94127181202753,9.88254410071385,19.7654476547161,29.6570558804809,
34.6026871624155,39.5483145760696,44.2786686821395,49.0090364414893,53.7399051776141,
58.4707259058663,63.1990074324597,65.5632458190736,67.9274788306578,70.2912795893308,
72.6550719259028,75.0187134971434,76.2005134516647,77.3823071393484,78.0386109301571,
78.6949190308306,79.3512896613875,80.0076600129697,81.3297035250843,82.6514040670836,
83.3171575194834,83.9828904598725,84.6494633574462,85.3160100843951,85.9782975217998,
86.6407235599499,87.3016869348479,87.9622444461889,88.4581264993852,88.954028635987,
89.4478324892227,89.9415713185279,90.440094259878,90.9386233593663,91.4386178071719,
91.9387301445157,92.6936197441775,93.449094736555,93.8286136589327,94.2081368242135,
94.5874895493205,94.9668268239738,95.8715470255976,96.7764761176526,97.6821007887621,
98.5876479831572,99.4954265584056,100.403221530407,101.310621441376,102.218028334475,
104.036405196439,105.854967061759,107.670709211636,109.486387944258,111.285157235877,
113.083928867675,116.681492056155,120.279169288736,123.876850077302,127.476759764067,
131.076672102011,138.276381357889,145.458783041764,152.641213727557,159.822501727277,
167.003782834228,170.387173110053,173.770648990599,177.156746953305,180.542759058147),.UNSPECIFIED.);
#611=CARTESIAN_POINT('',(29.5803989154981,5.,17.));
#612=VERTEX_POINT('',#611);
#613=EDGE_CURVE('E353',#612,#440,#610,.T.);
#614=ORIENTED_EDGE('',*,*,#613,.F.);
#615=CARTESIAN_POINT('',(0.,0.,17.));
#616=DIRECTION('',(0.,0.,1.));
#617=DIRECTION('',(1.,0.,0.));
#618=AXIS2_PLACEMENT_3D('',#615,#616,#617);
#619=CIRCLE('',#618,30.);
#620=CARTESIAN_POINT('',(-29.5803989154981,5.,17.));
#621=VERTEX_POINT('',#620);
#622=EDGE_CURVE('E257',#621,#612,#619,.F.);
#623=ORIENTED_EDGE('',*,*,#622,.F.);
#624=EDGE_CURVE('E275',#442,#621,#610,.T.);
#625=ORIENTED_EDGE('',*,*,#624,.F.);
#626=ORIENTED_EDGE('',*,*,#450,.F.);
#627=EDGE_LOOP('',(#614,#623,#625,#626));
#628=FACE_BOUND('',#627,.T.);
#629=ADVANCED_FACE('F303',(#628),#459,.T.);
#630=CARTESIAN_POINT('',(0.,0.,20.));
#631=DIRECTION('',(0.,0.,-1.));
#632=DIRECTION('',(-1.,0.,0.));
#633=AXIS2_PLACEMENT_3D('',#630,#631,#632);
#634=CYLINDRICAL_SURFACE('',#633,30.);
#635=CARTESIAN_POINT('',(0.,0.,10.));
#636=DIRECTION('',(0.,0.,1.));
#637=DIRECTION('',(1.,0.,0.));
#638=AXIS2_PLACEMENT_3D('',#635,#636,#637);
#639=CIRCLE('',#638,30.);
#640=CARTESIAN_POINT('',(-29.5803989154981,5.,10.));
#641=VERTEX_POINT('',#640);
#642=CARTESIAN_POINT('',(-29.5803989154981,-5.,10.));
#643=VERTEX_POINT('',#642);
#644=EDGE_CURVE('E351',#641,#643,#639,.T.);
#645=ORIENTED_EDGE('',*,*,#644,.F.);
#646=DIRECTION('',(0.,0.,-1.));
#647=VECTOR('',#646,1.);
#648=CARTESIAN_POINT('',(-29.5803989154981,5.,20.));
#649=LINE('',#648,#647);
#650=EDGE_CURVE('E247',#641,#621,#649,.F.);
#651=ORIENTED_EDGE('',*,*,#650,.T.);
#652=ORIENTED_EDGE('',*,*,#622,.T.);
#653=DIRECTION('',(0.,0.,-1.));
#654=VECTOR('',#653,1.);
#655=CARTESIAN_POINT('',(29.5803989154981,5.,20.));
#656=LINE('',#655,#654);
#657=CARTESIAN_POINT('',(29.5803989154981,5.,10.));
#658=VERTEX_POINT('',#657);
#659=EDGE_CURVE('E250',#612,#658,#656,.T.);
#660=ORIENTED_EDGE('',*,*,#659,.T.);
#661=CARTESIAN_POINT('',(29.5803989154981,-5.,10.));
#662=VERTEX_POINT('',#661);
#663=EDGE_CURVE('E352',#662,#658,#639,.T.);
#664=ORIENTED_EDGE('',*,*,#663,.F.);
#665=DIRECTION('',(0.,0.,-1.));
#666=VECTOR('',#665,1.);
#667=CARTESIAN_POINT('',(29.5803989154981,-5.,20.));
#668=LINE('',#667,#666);
#669=CARTESIAN_POINT('',(29.5803989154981,-5.,17.));
#670=VERTEX_POINT('',#669);
#671=EDGE_CURVE('E239',#662,#670,#668,.F.);
#672=ORIENTED_EDGE('',*,*,#671,.T.);
#673=CARTESIAN_POINT('',(-29.5803989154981,-5.,17.));
#674=VERTEX_POINT('',#673);
#675=EDGE_CURVE('E258',#670,#674,#619,.F.);
#676=ORIENTED_EDGE('',*,*,#675,.T.);
#677=DIRECTION('',(0.,0.,-1.));
#678=VECTOR('',#677,1.);
#679=CARTESIAN_POINT('',(-29.5803989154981,-5.,20.));
#680=LINE('',#679,#678);
#681=EDGE_CURVE('E244',#674,#643,#680,.T.);
#682=ORIENTED_EDGE('',*,*,#681,.T.);
#683=EDGE_LOOP('',(#645,#651,#652,#660,#664,#672,#676,#682));
#684=FACE_BOUND('',#683,.T.);
#685=CARTESIAN_POINT('',(0.,0.,2.99999999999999));
#686=DIRECTION('',(0.,0.,1.));
#687=DIRECTION('',(1.,0.,0.));
#688=AXIS2_PLACEMENT_3D('',#685,#686,#687);
#689=CIRCLE('',#688,30.);
#690=CARTESIAN_POINT('',(30.,0.,2.99999999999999));
#691=VERTEX_POINT('',#690);
#692=EDGE_CURVE('E261',#691,#691,#689,.T.);
#693=ORIENTED_EDGE('',*,*,#692,.T.);
#694=EDGE_LOOP('',(#693));
#695=FACE_BOUND('',#694,.T.);
#696=ADVANCED_FACE('F295',(#684,#695),#634,.T.);
#697=DIRECTION('',(1.,0.,0.));
#698=VECTOR('',#697,1.);
#699=CARTESIAN_POINT('',(-31.8396190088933,-5.,20.));
#700=LINE('',#699,#698);
#701=CARTESIAN_POINT('',(-26.5329983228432,-5.,20.));
#702=VERTEX_POINT('',#701);
#703=CARTESIAN_POINT('',(26.5329983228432,-5.,20.));
#704=VERTEX_POINT('',#703);
#705=EDGE_CURVE('E230',#702,#704,#700,.T.);
#706=ORIENTED_EDGE('',*,*,#705,.F.);
#707=EDGE_CURVE('E253',#702,#704,#449,.T.);
#708=ORIENTED_EDGE('',*,*,#707,.T.);
#709=EDGE_LOOP('',(#706,#708));
#710=FACE_BOUND('',#709,.T.);
#711=ADVANCED_FACE('F292',(#710),#434,.T.);
#712=CARTESIAN_POINT('',(-65.8556355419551,-5.,-19.0451719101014));
#713=CARTESIAN_POINT('',(-64.68929328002,-5.,-17.8821787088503));
#714=CARTESIAN_POINT('',(-63.5228644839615,-5.,-16.7192722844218));
#715=CARTESIAN_POINT('',(-61.1897976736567,-5.,-14.393669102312));
#716=CARTESIAN_POINT('',(-60.0231596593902,-5.,-13.2309723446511));
#717=CARTESIAN_POINT('',(-56.5227931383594,-5.,-9.74316661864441));
#718=CARTESIAN_POINT('',(-54.1886968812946,-5.,-7.41842669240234));
#719=CARTESIAN_POINT('',(-49.5170329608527,-5.,-2.76832103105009));
#720=CARTESIAN_POINT('',(-47.1794640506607,-5.,-0.442956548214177));
#721=CARTESIAN_POINT('',(-43.6715021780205,-5.,3.04339004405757));
#722=CARTESIAN_POINT('',(-42.5019339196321,-5.,4.20520193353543));
#723=CARTESIAN_POINT('',(-40.1620907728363,-5.,6.52811218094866));
#724=CARTESIAN_POINT('',(-38.9918158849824,-5.,7.6892105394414));
#725=CARTESIAN_POINT('',(-36.7013079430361,-5.,9.95996136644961));
#726=CARTESIAN_POINT('',(-35.5811139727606,-5.,11.0696532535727));
#727=CARTESIAN_POINT('',(-33.3396170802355,-5.,13.2879231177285));
#728=CARTESIAN_POINT('',(-32.2183141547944,-5.,14.3965010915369));
#729=CARTESIAN_POINT('',(-29.9740960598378,-5.,16.612262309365));
#730=CARTESIAN_POINT('',(-28.8511807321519,-5.,17.7194453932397));
#731=CARTESIAN_POINT('',(-26.6032702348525,-5.,19.9316758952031));
#732=CARTESIAN_POINT('',(-25.4782750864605,-5.,21.03672333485));
#733=CARTESIAN_POINT('',(-23.2258575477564,-5.,23.2431345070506));
#734=CARTESIAN_POINT('',(-22.0984367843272,-5.,24.3444998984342));
#735=CARTESIAN_POINT('',(-20.4037555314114,-5.,25.9929457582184));
#736=CARTESIAN_POINT('',(-19.8382583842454,-5.,26.5418386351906));
#737=CARTESIAN_POINT('',(-18.7057501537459,-5.,27.6380584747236));
#738=CARTESIAN_POINT('',(-18.1387390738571,-5.,28.1853854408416));
#739=CARTESIAN_POINT('',(-17.0028555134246,-5.,29.2778978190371));
#740=CARTESIAN_POINT('',(-16.4339833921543,-5.,29.8230836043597));
#741=CARTESIAN_POINT('',(-15.2936191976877,-5.,30.9107058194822));
#742=CARTESIAN_POINT('',(-14.7221271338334,-5.,31.4531422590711));
#743=CARTESIAN_POINT('',(-13.5755888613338,-5.,32.5341815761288));
#744=CARTESIAN_POINT('',(-13.0005428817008,-5.,33.0727846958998));
#745=CARTESIAN_POINT('',(-12.1341242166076,-5.,33.8765296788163));
#746=CARTESIAN_POINT('',(-11.8446789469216,-5.,34.1437490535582));
#747=CARTESIAN_POINT('',(-11.2642175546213,-5.,34.6764753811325));
#748=CARTESIAN_POINT('',(-10.973201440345,-5.,34.9419823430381));
#749=CARTESIAN_POINT('',(-10.5190691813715,-5.,35.3532789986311));
#750=CARTESIAN_POINT('',(-10.3566207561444,-5.,35.4998061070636));
#751=CARTESIAN_POINT('',(-10.0310484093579,-5.,35.7921104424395));
#752=CARTESIAN_POINT('',(-9.86792448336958,-5.,35.937887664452));
#753=CARTESIAN_POINT('',(-9.5408974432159,-5.,36.2285975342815));
#754=CARTESIAN_POINT('',(-9.37699425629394,-5.,36.3735301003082));
#755=CARTESIAN_POINT('',(-9.04831656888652,-5.,36.6624035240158));
#756=CARTESIAN_POINT('',(-8.88354206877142,-5.,36.8063443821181));
#757=CARTESIAN_POINT('',(-8.38538551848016,-5.,37.2384859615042));
#758=CARTESIAN_POINT('',(-8.05048455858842,-5.,37.5249412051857));
#759=CARTESIAN_POINT('',(-7.37540456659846,-5.,38.091423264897));
#760=CARTESIAN_POINT('',(-7.03522692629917,-5.,38.3714517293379));
#761=CARTESIAN_POINT('',(-6.51816738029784,-5.,38.7856310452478));
#762=CARTESIAN_POINT('',(-6.34403051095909,-5.,38.9232073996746));
#763=CARTESIAN_POINT('',(-5.99353583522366,-5.,39.1954972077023));
#764=CARTESIAN_POINT('',(-5.81717809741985,-5.,39.3302107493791));
#765=CARTESIAN_POINT('',(-5.46159323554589,-5.,39.5962799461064));
#766=CARTESIAN_POINT('',(-5.28236277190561,-5.,39.7276311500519));
#767=CARTESIAN_POINT('',(-4.92073426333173,-5.,39.9859001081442));
#768=CARTESIAN_POINT('',(-4.73833634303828,-5.,40.1128180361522));
#769=CARTESIAN_POINT('',(-4.37091006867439,-5.,40.3602322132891));
#770=CARTESIAN_POINT('',(-4.18590597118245,-5.,40.4807643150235));
#771=CARTESIAN_POINT('',(-3.81135724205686,-5.,40.7146966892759));
#772=CARTESIAN_POINT('',(-3.62181166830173,-5.,40.8280954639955));
#773=CARTESIAN_POINT('',(-3.23781372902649,-5.,41.0453031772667));
#774=CARTESIAN_POINT('',(-3.0433731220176,-5.,41.149132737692));
#775=CARTESIAN_POINT('',(-2.64845385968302,-5.,41.3444823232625));
#776=CARTESIAN_POINT('',(-2.44797898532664,-5.,41.4360098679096));
#777=CARTESIAN_POINT('',(-2.09118241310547,-5.,41.5821043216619));
#778=CARTESIAN_POINT('',(-1.93631281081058,-5.,41.6401970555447));
#779=CARTESIAN_POINT('',(-1.6228046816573,-5.,41.7453167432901));
#780=CARTESIAN_POINT('',(-1.46416600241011,-5.,41.7923432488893));
#781=CARTESIAN_POINT('',(-1.14419944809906,-5.,41.8730754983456));
#782=CARTESIAN_POINT('',(-0.982885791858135,-5.,41.9068367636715));
#783=CARTESIAN_POINT('',(-0.657825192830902,-5.,41.9594604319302));
#784=CARTESIAN_POINT('',(-0.494078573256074,-5.,41.978324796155));
#785=CARTESIAN_POINT('',(-0.163910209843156,-5.,42.0000512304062));
#786=CARTESIAN_POINT('',(0.00252208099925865,-5.,42.0027564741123));
#787=CARTESIAN_POINT('',(0.334816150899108,-5.,41.9915552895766));
#788=CARTESIAN_POINT('',(0.500677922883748,-5.,41.9776486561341));
#789=CARTESIAN_POINT('',(0.830782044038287,-5.,41.9341014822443));
#790=CARTESIAN_POINT('',(0.995018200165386,-5.,41.9044148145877));
#791=CARTESIAN_POINT('',(1.32031294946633,-5.,41.83104631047));
#792=CARTESIAN_POINT('',(1.48137078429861,-5.,41.7873611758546));
#793=CARTESIAN_POINT('',(1.88086272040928,-5.,41.662821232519));
#794=CARTESIAN_POINT('',(2.11691618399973,-5.,41.5743682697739));
#795=CARTESIAN_POINT('',(2.58043788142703,-5.,41.377322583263));
#796=CARTESIAN_POINT('',(2.80789931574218,-5.,41.2687142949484));
#797=CARTESIAN_POINT('',(3.14380644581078,-5.,41.094549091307));
#798=CARTESIAN_POINT('',(3.25514910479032,-5.,41.0344645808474));
#799=CARTESIAN_POINT('',(3.4760604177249,-5.,40.9111096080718));
#800=CARTESIAN_POINT('',(3.58562905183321,-5.,40.8478391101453));
#801=CARTESIAN_POINT('',(3.80309504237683,-5.,40.718607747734));
#802=CARTESIAN_POINT('',(3.91099312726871,-5.,40.6526481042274));
#803=CARTESIAN_POINT('',(4.12531480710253,-5.,40.5183907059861));
#804=CARTESIAN_POINT('',(4.2317384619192,-5.,40.4500930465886));
#805=CARTESIAN_POINT('',(4.5897555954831,-5.,40.2155017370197));
#806=CARTESIAN_POINT('',(4.83826444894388,-5.,40.0444941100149));
#807=CARTESIAN_POINT('',(5.32945766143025,-5.,39.6942796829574));
#808=CARTESIAN_POINT('',(5.572140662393,-5.,39.515070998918));
#809=CARTESIAN_POINT('',(6.05308761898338,-5.,39.1504602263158));
#810=CARTESIAN_POINT('',(6.29134803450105,-5.,38.9650534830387));
#811=CARTESIAN_POINT('',(6.76419305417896,-5.,38.5896689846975));
#812=CARTESIAN_POINT('',(6.9987779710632,-5.,38.3996916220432));
#813=CARTESIAN_POINT('',(7.46559346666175,-5.,38.0157116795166));
#814=CARTESIAN_POINT('',(7.69781681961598,-5.,37.8217003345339));
#815=CARTESIAN_POINT('',(8.15988097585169,-5.,37.4308577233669));
#816=CARTESIAN_POINT('',(8.38972173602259,-5.,37.234026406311));
#817=CARTESIAN_POINT('',(8.84734688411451,-5.,36.8381906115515));
#818=CARTESIAN_POINT('',(9.07513212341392,-5.,36.6391871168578));
#819=CARTESIAN_POINT('',(9.52908055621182,-5.,36.2393373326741));
#820=CARTESIAN_POINT('',(9.75524373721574,-5.,36.0384910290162));
#821=CARTESIAN_POINT('',(10.4325949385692,-5.,35.432897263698));
#822=CARTESIAN_POINT('',(10.8817485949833,-5.,35.025874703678));
#823=CARTESIAN_POINT('',(11.776212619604,-5.,34.2075509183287));
#824=CARTESIAN_POINT('',(12.2215225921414,-5.,33.7962492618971));
#825=CARTESIAN_POINT('',(13.1085597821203,-5.,32.971176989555));
#826=CARTESIAN_POINT('',(13.5502914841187,-5.,32.5574111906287));
#827=CARTESIAN_POINT('',(14.4315399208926,-5.,31.7275608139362));
#828=CARTESIAN_POINT('',(14.8710567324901,-5.,31.3114763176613));
#829=CARTESIAN_POINT('',(15.7442912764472,-5.,30.4813888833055));
#830=CARTESIAN_POINT('',(16.1780248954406,-5.,30.0674026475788));
#831=CARTESIAN_POINT('',(17.0441516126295,-5.,29.238029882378));
#832=CARTESIAN_POINT('',(17.4765447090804,-5.,28.8226433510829));
#833=CARTESIAN_POINT('',(18.7721181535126,-5.,27.5748071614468));
#834=CARTESIAN_POINT('',(19.6336878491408,-5.,26.7406854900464));
#835=CARTESIAN_POINT('',(21.3539494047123,-5.,25.0694293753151));
#836=CARTESIAN_POINT('',(22.2126411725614,-5.,24.2322948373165));
#837=CARTESIAN_POINT('',(23.9279511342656,-5.,22.5559030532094));
#838=CARTESIAN_POINT('',(24.7845693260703,-5.,21.7166458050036));
#839=CARTESIAN_POINT('',(26.4968110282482,-5.,20.0360578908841));
#840=CARTESIAN_POINT('',(27.3524335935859,-5.,19.1947262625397));
#841=CARTESIAN_POINT('',(29.0625198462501,-5.,17.5108850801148));
#842=CARTESIAN_POINT('',(29.9169835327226,-5.,16.6683755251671));
#843=CARTESIAN_POINT('',(32.4790160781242,-5.,14.1395254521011));
#844=CARTESIAN_POINT('',(34.1852538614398,-5.,12.4518365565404));
#845=CARTESIAN_POINT('',(37.5913921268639,-5.,9.07825999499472));
#846=CARTESIAN_POINT('',(39.2912979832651,-5.,7.39237775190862));
#847=CARTESIAN_POINT('',(42.6895996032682,-5.,4.01907843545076));
#848=CARTESIAN_POINT('',(44.3879953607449,-5.,2.33166135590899));
#849=CARTESIAN_POINT('',(47.7834450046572,-5.,-1.0439821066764));
#850=CARTESIAN_POINT('',(49.4804990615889,-5.,-2.7322083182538));
#851=CARTESIAN_POINT('',(52.8738193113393,-5.,-6.10944904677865));
#852=CARTESIAN_POINT('',(54.5700855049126,-5.,-7.79846356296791));
#853=CARTESIAN_POINT('',(57.0650936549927,-5.,-10.2836796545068));
#854=CARTESIAN_POINT('',(57.8640668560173,-5.,-11.0796491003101));
#855=CARTESIAN_POINT('',(59.461916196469,-5.,-12.6717258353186));
#856=CARTESIAN_POINT('',(60.2607923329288,-5.,-13.467833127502));
#857=CARTESIAN_POINT('',(61.8590598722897,-5.,-15.0607688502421));
#858=CARTESIAN_POINT('',(62.6584511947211,-5.,-15.8575973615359));
#859=CARTESIAN_POINT('',(64.2571205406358,-5.,-17.4513274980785));
#860=CARTESIAN_POINT('',(65.0563985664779,-5.,-18.2482291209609));
#861=CARTESIAN_POINT('',(65.8556355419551,-5.,-19.0451719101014));
#862=B_SPLINE_CURVE_WITH_KNOTS('',3,(#712,#713,#714,#715,#716,#717,#718,#719,#720,#721,#722,
#723,#724,#725,#726,#727,#728,#729,#730,#731,#732,#733,#734,#735,#736,#737,#738,#739,#740,#741,
#742,#743,#744,#745,#746,#747,#748,#749,#750,#751,#752,#753,#754,#755,#756,#757,#758,#759,#760,
#761,#762,#763,#764,#765,#766,#767,#768,#769,#770,#771,#772,#773,#774,#775,#776,#777,#778,#779,
#780,#781,#782,#783,#784,#785,#786,#787,#788,#789,#790,#791,#792,#793,#794,#795,#796,#797,#798,
#799,#800,#801,#802,#803,#804,#805,#806,#807,#808,#809,#810,#811,#812,#813,#814,#815,#816,#817,
#818,#819,#820,#821,#822,#823,#824,#825,#826,#827,#828,#829,#830,#831,#832,#833,#834,#835,#836,
#837,#838,#839,#840,#841,#842,#843,#844,#845,#846,#847,#848,#849,#850,#851,#852,#853,#854,#855,
#856,#857,#858,#859,#860,#861),.UNSPECIFIED.,.F.,.F.,(4,2,2,2,2,2,2,2,2,2,2,2,2,2,2,2,2,2,2,2,2,
2,2,2,2,2,2,2,2,2,2,2,2,2,2,2,2,2,2,2,2,2,2,2,2,2,2,2,2,2,2,2,2,2,2,2,2,2,2,2,2,2,2,2,2,2,2,2,2,
2,2,2,2,2,4),(0.,4.94127181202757,9.88254410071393,19.7654476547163,29.6570558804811,
34.6026871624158,39.5483145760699,44.2786686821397,49.0090364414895,53.7399051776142,
58.4707259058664,63.1990074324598,65.5632458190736,67.9274788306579,70.2912795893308,
72.6550719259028,75.0187134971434,76.2005134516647,77.3823071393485,78.0386109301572,
78.6949190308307,79.3512896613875,80.0076600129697,81.3297035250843,82.6514040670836,
83.3171575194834,83.9828904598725,84.6494633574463,85.3160100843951,85.9782975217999,
86.6407235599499,87.3016869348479,87.9622444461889,88.4581264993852,88.954028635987,
89.4478324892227,89.9415713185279,90.440094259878,90.9386233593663,91.4386178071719,
91.9387301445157,92.6936197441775,93.449094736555,93.8286136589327,94.2081368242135,
94.5874895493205,94.9668268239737,95.8715470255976,96.7764761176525,97.682100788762,
98.5876479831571,99.4954265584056,100.403221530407,101.310621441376,102.218028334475,
104.036405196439,105.854967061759,107.670709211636,109.486387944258,111.285157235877,
113.083928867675,116.681492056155,120.279169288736,123.876850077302,127.476759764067,
131.07667210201,138.276381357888,145.458783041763,152.641213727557,159.822501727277,
167.003782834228,170.387173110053,173.770648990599,177.156746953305,180.542759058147),.UNSPECIFIED.);
#863=EDGE_CURVE('E274',#674,#702,#862,.T.);
#864=ORIENTED_EDGE('',*,*,#863,.F.);
#865=ORIENTED_EDGE('',*,*,#675,.F.);
#866=EDGE_CURVE('E267',#704,#670,#862,.T.);
#867=ORIENTED_EDGE('',*,*,#866,.F.);
#868=ORIENTED_EDGE('',*,*,#707,.F.);
#869=EDGE_LOOP('',(#864,#865,#867,#868));
#870=FACE_BOUND('',#869,.T.);
#871=ADVANCED_FACE('F281',(#870),#459,.T.);
#872=CARTESIAN_POINT('',(0.,0.,2.99999999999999));
#873=DIRECTION('',(0.,0.,1.));
#874=DIRECTION('',(1.,0.,0.));
#875=AXIS2_PLACEMENT_3D('',#872,#873,#874);
#876=CONICAL_SURFACE('',#875,30.,0.785398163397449);
#877=CARTESIAN_POINT('',(27.,0.,0.));
#878=CARTESIAN_POINT('',(27.03125,0.,0.0312499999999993));
#879=CARTESIAN_POINT('',(27.0625,0.,0.0624999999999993));
#880=CARTESIAN_POINT('',(27.125,0.,0.124999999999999));
#881=CARTESIAN_POINT('',(27.15625,0.,0.156249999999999));
#882=CARTESIAN_POINT('',(27.21875,0.,0.218749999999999));
#883=CARTESIAN_POINT('',(27.25,0.,0.249999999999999));
#884=CARTESIAN_POINT('',(27.3125,0.,0.312499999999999));
#885=CARTESIAN_POINT('',(27.34375,0.,0.343749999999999));
#886=CARTESIAN_POINT('',(27.40625,0.,0.406249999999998));
#887=CARTESIAN_POINT('',(27.4375,0.,0.437499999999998));
#888=CARTESIAN_POINT('',(27.5,0.,0.499999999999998));
#889=CARTESIAN_POINT('',(27.53125,0.,0.531249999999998));
#890=CARTESIAN_POINT('',(27.59375,0.,0.593749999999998));
#891=CARTESIAN_POINT('',(27.625,0.,0.624999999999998));
#892=CARTESIAN_POINT('',(27.6875,0.,0.687499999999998));
#893=CARTESIAN_POINT('',(27.71875,0.,0.718749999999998));
#894=CARTESIAN_POINT('',(27.78125,0.,0.781249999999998));
#895=CARTESIAN_POINT('',(27.8125,0.,0.812499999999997));
#896=CARTESIAN_POINT('',(27.875,0.,0.874999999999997));
#897=CARTESIAN_POINT('',(27.90625,0.,0.906249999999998));
#898=CARTESIAN_POINT('',(27.96875,0.,0.968749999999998));
#899=CARTESIAN_POINT('',(28.,0.,0.999999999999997));
#900=CARTESIAN_POINT('',(28.0625,0.,1.0625));
#901=CARTESIAN_POINT('',(28.09375,0.,1.09375));
#902=CARTESIAN_POINT('',(28.15625,0.,1.15625));
#903=CARTESIAN_POINT('',(28.1875,0.,1.1875));
#904=CARTESIAN_POINT('',(28.25,0.,1.25));
#905=CARTESIAN_POINT('',(28.28125,0.,1.28125));
#906=CARTESIAN_POINT('',(28.34375,0.,1.34375));
#907=CARTESIAN_POINT('',(28.375,0.,1.375));
#908=CARTESIAN_POINT('',(28.4375,0.,1.4375));
#909=CARTESIAN_POINT('',(28.46875,0.,1.46875));
#910=CARTESIAN_POINT('',(28.53125,0.,1.53125));
#911=CARTESIAN_POINT('',(28.5625,0.,1.5625));
#912=CARTESIAN_POINT('',(28.625,0.,1.625));
#913=CARTESIAN_POINT('',(28.65625,0.,1.65625));
#914=CARTESIAN_POINT('',(28.71875,0.,1.71875));
#915=CARTESIAN_POINT('',(28.75,0.,1.75));
#916=CARTESIAN_POINT('',(28.8125,0.,1.8125));
#917=CARTESIAN_POINT('',(28.84375,0.,1.84375));
#918=CARTESIAN_POINT('',(28.90625,0.,1.90624999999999));
#919=CARTESIAN_POINT('',(28.9375,0.,1.93749999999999));
#920=CARTESIAN_POINT('',(29.,0.,1.99999999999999));
#921=CARTESIAN_POINT('',(29.03125,0.,2.03124999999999));
#922=CARTESIAN_POINT('',(29.09375,0.,2.09374999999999));
#923=CARTESIAN_POINT('',(29.125,0.,2.12499999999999));
#924=CARTESIAN_POINT('',(29.1875,0.,2.18749999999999));
#925=CARTESIAN_POINT('',(29.21875,0.,2.21874999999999));
#926=CARTESIAN_POINT('',(29.28125,0.,2.28124999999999));
#927=CARTESIAN_POINT('',(29.3125,0.,2.31249999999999));
#928=CARTESIAN_POINT('',(29.375,0.,2.37499999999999));
#929=CARTESIAN_POINT('',(29.40625,0.,2.40624999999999));
#930=CARTESIAN_POINT('',(29.46875,0.,2.46874999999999));
#931=CARTESIAN_POINT('',(29.5,0.,2.49999999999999));
#932=CARTESIAN_POINT('',(29.5625,0.,2.56249999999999));
#933=CARTESIAN_POINT('',(29.59375,0.,2.59374999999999));
#934=CARTESIAN_POINT('',(29.65625,0.,2.65624999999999));
#935=CARTESIAN_POINT('',(29.6875,0.,2.68749999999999));
#936=CARTESIAN_POINT('',(29.75,0.,2.74999999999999));
#937=CARTESIAN_POINT('',(29.78125,0.,2.78124999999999));
#938=CARTESIAN_POINT('',(29.84375,0.,2.84374999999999));
#939=CARTESIAN_POINT('',(29.875,0.,2.87499999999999));
#940=CARTESIAN_POINT('',(29.9375,0.,2.93749999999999));
#941=CARTESIAN_POINT('',(29.96875,0.,2.96874999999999));
#942=CARTESIAN_POINT('',(30.,0.,2.99999999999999));
#943=B_SPLINE_CURVE_WITH_KNOTS('',3,(#877,#878,#879,#880,#881,#882,#883,#884,#885,#886,#887,
#888,#889,#890,#891,#892,#893,#894,#895,#896,#897,#898,#899,#900,#901,#902,#903,#904,#905,#906,
#907,#908,#909,#910,#911,#912,#913,#914,#915,#916,#917,#918,#919,#920,#921,#922,#923,#924,#925,
#926,#927,#928,#929,#930,#931,#932,#933,#934,#935,#936,#937,#938,#939,#940,#941,#942),
.UNSPECIFIED.,.F.,.F.,(4,2,2,2,2,2,2,2,2,2,2,2,2,2,2,2,2,2,2,2,2,2,2,2,2,2,2,2,2,2,2,2,4),(0.,
0.132582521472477,0.265165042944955,0.397747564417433,0.53033008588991,0.662912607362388,
0.795495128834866,0.928077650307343,1.06066017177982,1.1932426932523,1.32582521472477,
1.45840773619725,1.59099025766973,1.72357277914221,1.85615530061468,1.98873782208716,
2.12132034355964,2.25390286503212,2.38648538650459,2.51906790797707,2.65165042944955,
2.78423295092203,2.9168154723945,3.04939799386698,3.18198051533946,3.31456303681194,
3.44714555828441,3.57972807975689,3.71231060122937,3.84489312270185,3.97747564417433,
4.1100581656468,4.24264068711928),.UNSPECIFIED.);
#944=EDGE_CURVE('BSEAM403',#421,#691,#943,.T.);
#945=ORIENTED_EDGE('',*,*,#422,.F.);
#946=ORIENTED_EDGE('',*,*,#692,.F.);
#947=ORIENTED_EDGE('',*,*,#944,.T.);
#948=ORIENTED_EDGE('',*,*,#944,.F.);
#949=EDGE_LOOP('',(#945,#947,#946,#948));
#950=FACE_BOUND('',#949,.T.);
#951=ADVANCED_FACE('F403',(#950),#876,.T.);
#952=CARTESIAN_POINT('',(0.,0.,10.));
#953=DIRECTION('',(0.,0.,1.));
#954=DIRECTION('',(1.,0.,0.));
#955=AXIS2_PLACEMENT_3D('',#952,#953,#954);
#956=PLANE('',#955);
#957=ORIENTED_EDGE('',*,*,#644,.T.);
#958=DIRECTION('',(1.,0.,0.));
#959=VECTOR('',#958,1.);
#960=CARTESIAN_POINT('',(-31.8396190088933,-5.,10.));
#961=LINE('',#960,#959);
#962=EDGE_CURVE('E232',#643,#662,#961,.T.);
#963=ORIENTED_EDGE('',*,*,#962,.T.);
#964=ORIENTED_EDGE('',*,*,#663,.T.);
#965=DIRECTION('',(-1.,0.,0.));
#966=VECTOR('',#965,1.);
#967=CARTESIAN_POINT('',(-31.8396190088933,5.,10.));
#968=LINE('',#967,#966);
#969=EDGE_CURVE('E235',#658,#641,#968,.T.);
#970=ORIENTED_EDGE('',*,*,#969,.T.);
#971=EDGE_LOOP('',(#957,#963,#964,#970));
#972=FACE_BOUND('',#971,.T.);
#973=ADVANCED_FACE('F326',(#972),#956,.T.);
#974=CARTESIAN_POINT('',(-31.8396190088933,5.,10.));
#975=DIRECTION('',(0.,1.,0.));
#976=DIRECTION('',(0.,0.,1.));
#977=AXIS2_PLACEMENT_3D('',#974,#975,#976);
#978=PLANE('',#977);
#979=ORIENTED_EDGE('',*,*,#613,.T.);
#980=ORIENTED_EDGE('',*,*,#443,.T.);
#981=ORIENTED_EDGE('',*,*,#624,.T.);
#982=ORIENTED_EDGE('',*,*,#650,.F.);
#983=ORIENTED_EDGE('',*,*,#969,.F.);
#984=ORIENTED_EDGE('',*,*,#659,.F.);
#985=EDGE_LOOP('',(#979,#980,#981,#982,#983,#984));
#986=FACE_BOUND('',#985,.T.);
#987=ADVANCED_FACE('F288',(#986),#978,.F.);
#988=CARTESIAN_POINT('',(-31.8396190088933,-5.,10.));
#989=DIRECTION('',(0.,-1.,0.));
#990=DIRECTION('',(0.,0.,-1.));
#991=AXIS2_PLACEMENT_3D('',#988,#989,#990);
#992=PLANE('',#991);
#993=ORIENTED_EDGE('',*,*,#863,.T.);
#994=ORIENTED_EDGE('',*,*,#705,.T.);
#995=ORIENTED_EDGE('',*,*,#866,.T.);
#996=ORIENTED_EDGE('',*,*,#671,.F.);
#997=ORIENTED_EDGE('',*,*,#962,.F.);
#998=ORIENTED_EDGE('',*,*,#681,.F.);
#999=EDGE_LOOP('',(#993,#994,#995,#996,#997,#998));
#1000=FACE_BOUND('',#999,.T.);
#1001=ADVANCED_FACE('F284',(#1000),#992,.F.);
#1002=CARTESIAN_POINT('',(0.,0.,-60.));
#1003=DIRECTION('',(0.,0.,1.));
#1004=DIRECTION('',(1.,0.,0.));
#1005=AXIS2_PLACEMENT_3D('',#1002,#1003,#1004);
#1006=CONICAL_SURFACE('',#1005,7.00000000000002,0.785398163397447);
#1007=ORIENTED_EDGE('',*,*,#349,.F.);
#1008=EDGE_LOOP('',(#1007));
#1009=FACE_BOUND('',#1008,.T.);
#1010=ORIENTED_EDGE('',*,*,#31,.F.);
#1011=EDGE_LOOP('',(#1010));
#1012=FACE_BOUND('',#1011,.T.);
#1013=ADVANCED_FACE('F36',(#1009,#1012),#1006,.T.);
#1014=CARTESIAN_POINT('',(-17.,-1.25,-44.1229626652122));
#1015=DIRECTION('',(0.,1.,0.));
#1016=DIRECTION('',(0.,0.,1.));
#1017=AXIS2_PLACEMENT_3D('',#1014,#1015,#1016);
#1018=CYLINDRICAL_SURFACE('',#1017,10.);
#1019=CARTESIAN_POINT('',(-17.,-1.25,-44.1229626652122));
#1020=DIRECTION('',(0.,1.,0.));
#1021=DIRECTION('',(0.,0.,1.));
#1022=AXIS2_PLACEMENT_3D('',#1019,#1020,#1021);
#1023=CIRCLE('',#1022,10.);
#1024=EDGE_CURVE('E223',#360,#358,#1023,.T.);
#1025=ORIENTED_EDGE('',*,*,#1024,.F.);
#1026=ORIENTED_EDGE('',*,*,#405,.F.);
#1027=CARTESIAN_POINT('',(-17.,1.25,-44.1229626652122));
#1028=DIRECTION('',(0.,1.,0.));
#1029=DIRECTION('',(0.,0.,1.));
#1030=AXIS2_PLACEMENT_3D('',#1027,#1028,#1029);
#1031=CIRCLE('',#1030,10.);
#1032=EDGE_CURVE('E56',#387,#379,#1031,.T.);
#1033=ORIENTED_EDGE('',*,*,#1032,.T.);
#1034=ORIENTED_EDGE('',*,*,#380,.F.);
#1035=EDGE_LOOP('',(#1025,#1026,#1033,#1034));
#1036=FACE_BOUND('',#1035,.T.);
#1037=ADVANCED_FACE('F322',(#1036),#1018,.F.);
#1038=CARTESIAN_POINT('',(-17.,-1.25,-44.1229626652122));
#1039=DIRECTION('',(0.,1.,0.));
#1040=DIRECTION('',(0.,0.,1.));
#1041=AXIS2_PLACEMENT_3D('',#1038,#1039,#1040);
#1042=PLANE('',#1041);
#1043=ORIENTED_EDGE('',*,*,#361,.T.);
#1044=ORIENTED_EDGE('',*,*,#1024,.T.);
#1045=EDGE_LOOP('',(#1043,#1044));
#1046=FACE_BOUND('',#1045,.T.);
#1047=ADVANCED_FACE('F450',(#1046),#1042,.T.);
#1048=CARTESIAN_POINT('',(-17.,1.25,-44.1229626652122));
#1049=DIRECTION('',(0.,1.,0.));
#1050=DIRECTION('',(0.,0.,1.));
#1051=AXIS2_PLACEMENT_3D('',#1048,#1049,#1050);
#1052=PLANE('',#1051);
#1053=ORIENTED_EDGE('',*,*,#1032,.F.);
#1054=ORIENTED_EDGE('',*,*,#388,.F.);
#1055=EDGE_LOOP('',(#1053,#1054));
#1056=FACE_BOUND('',#1055,.T.);
#1057=ADVANCED_FACE('F459',(#1056),#1052,.F.);
#1058=CARTESIAN_POINT('',(0.427282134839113,-1.72050368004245,-59.));
#1059=CARTESIAN_POINT('',(0.453717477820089,-1.71999249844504,-59.));
#1060=CARTESIAN_POINT('',(0.506255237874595,-1.71897657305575,-59.));
#1061=CARTESIAN_POINT('',(0.583964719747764,-1.70999529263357,-59.));
#1062=CARTESIAN_POINT('',(0.660104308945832,-1.69728818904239,-59.));
#1063=CARTESIAN_POINT('',(0.733718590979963,-1.67711411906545,-59.));
#1064=CARTESIAN_POINT('',(0.805756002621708,-1.65263714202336,-59.));
#1065=CARTESIAN_POINT('',(0.875903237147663,-1.62249880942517,-59.));
#1066=CARTESIAN_POINT('',(0.944194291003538,-1.5863816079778,-59.));
#1067=CARTESIAN_POINT('',(1.01101187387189,-1.54508658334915,-59.));
#1068=CARTESIAN_POINT('',(1.07618604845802,-1.49702883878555,-59.));
#1069=CARTESIAN_POINT('',(1.13910551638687,-1.44105534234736,-59.));
#1070=CARTESIAN_POINT('',(1.20183470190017,-1.37870983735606,-59.));
#1071=CARTESIAN_POINT('',(1.26252209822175,-1.30829927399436,-59.));
#1072=CARTESIAN_POINT('',(1.32239524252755,-1.23096119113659,-59.));
#1073=CARTESIAN_POINT('',(1.38027365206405,-1.14597200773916,-59.));
#1074=CARTESIAN_POINT('',(1.43735536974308,-1.05379465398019,-59.));
#1075=CARTESIAN_POINT('',(1.47317083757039,-0.98892956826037,-59.));
#1076=CARTESIAN_POINT('',(1.4915850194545,-0.955579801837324,-59.));
#1077=B_SPLINE_CURVE_WITH_KNOTS('',3,(#1058,#1059,#1060,#1061,#1062,#1063,#1064,#1065,#1066,
#1067,#1068,#1069,#1070,#1071,#1072,#1073,#1074,#1075,#1076),.UNSPECIFIED.,.F.,.F.,(4,1,1,1,1,1,
1,1,1,1,1,1,1,1,1,1,4),(0.,0.0572082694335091,0.11369605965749,0.169177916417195,
0.224159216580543,0.278719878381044,0.333794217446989,0.389241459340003,0.445822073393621,
0.50370428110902,0.564293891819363,0.627975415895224,0.695038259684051,0.765372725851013,
0.839611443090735,0.917537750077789,1.),.UNSPECIFIED.);
#1078=DIRECTION('',(0.,0.,-1.));
#1079=VECTOR('',#1078,1.);
#1080=SURFACE_OF_LINEAR_EXTRUSION('',#1077,#1079);
#1081=ORIENTED_EDGE('',*,*,#83,.F.);
#1082=DIRECTION('',(0.,0.,-1.));
#1083=VECTOR('',#1082,1.);
#1084=CARTESIAN_POINT('',(0.427282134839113,-1.72050368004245,-59.));
#1085=LINE('',#1084,#1083);
#1086=CARTESIAN_POINT('',(0.427282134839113,-1.72050368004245,-59.));
#1087=VERTEX_POINT('',#1086);
#1088=EDGE_CURVE('E215',#1087,#58,#1085,.T.);
#1089=ORIENTED_EDGE('',*,*,#1088,.F.);
#1090=CARTESIAN_POINT('',(1.4915850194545,-0.955579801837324,-59.));
#1091=VERTEX_POINT('',#1090);
#1092=EDGE_CURVE('E206',#1087,#1091,#1077,.T.);
#1093=ORIENTED_EDGE('',*,*,#1092,.T.);
#1094=DIRECTION('',(0.,0.,-1.));
#1095=VECTOR('',#1094,1.);
#1096=CARTESIAN_POINT('',(1.4915850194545,-0.955579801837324,-59.));
#1097=LINE('',#1096,#1095);
#1098=EDGE_CURVE('E214',#1091,#82,#1097,.T.);
#1099=ORIENTED_EDGE('',*,*,#1098,.T.);
#1100=EDGE_LOOP('',(#1081,#1089,#1093,#1099));
#1101=FACE_BOUND('',#1100,.T.);
#1102=ADVANCED_FACE('F213',(#1101),#1080,.T.);
#1103=CARTESIAN_POINT('',(1.4915850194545,-0.955579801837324,-59.));
#1104=DIRECTION('',(-0.514196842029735,-0.857672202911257,0.));
#1105=DIRECTION('',(0.857672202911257,-0.514196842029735,0.));
#1106=AXIS2_PLACEMENT_3D('',#1103,#1104,#1105);
#1107=PLANE('',#1106);
#1108=ORIENTED_EDGE('',*,*,#91,.F.);
#1109=ORIENTED_EDGE('',*,*,#1098,.F.);
#1110=DIRECTION('',(-0.857672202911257,0.514196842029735,0.));
#1111=VECTOR('',#1110,1.);
#1112=CARTESIAN_POINT('',(1.4915850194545,-0.955579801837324,-59.));
#1113=LINE('',#1112,#1111);
#1114=CARTESIAN_POINT('',(1.1957116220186,-0.77819598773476,-59.));
#1115=VERTEX_POINT('',#1114);
#1116=EDGE_CURVE('E202',#1091,#1115,#1113,.T.);
#1117=ORIENTED_EDGE('',*,*,#1116,.T.);
#1118=DIRECTION('',(0.,0.,-1.));
#1119=VECTOR('',#1118,1.);
#1120=CARTESIAN_POINT('',(1.1957116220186,-0.77819598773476,-59.));
#1121=LINE('',#1120,#1119);
#1122=EDGE_CURVE('E221',#1115,#90,#1121,.T.);
#1123=ORIENTED_EDGE('',*,*,#1122,.T.);
#1124=EDGE_LOOP('',(#1108,#1109,#1117,#1123));
#1125=FACE_BOUND('',#1124,.T.);
#1126=ADVANCED_FACE('F218',(#1125),#1107,.T.);
#1127=CARTESIAN_POINT('',(1.1957116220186,-0.77819598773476,-59.));
#1128=CARTESIAN_POINT('',(1.16819338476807,-0.824260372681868,-59.));
#1129=CARTESIAN_POINT('',(1.11546950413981,-0.912517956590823,-59.));
#1130=CARTESIAN_POINT('',(1.02751814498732,-1.0317759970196,-59.));
#1131=CARTESIAN_POINT('',(0.9363852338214,-1.13313815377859,-59.));
#1132=CARTESIAN_POINT('',(0.841395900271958,-1.21601476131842,-59.));
#1133=CARTESIAN_POINT('',(0.743129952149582,-1.28126364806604,-59.));
#1134=CARTESIAN_POINT('',(0.640945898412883,-1.32746587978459,-59.));
#1135=CARTESIAN_POINT('',(0.535188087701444,-1.35628185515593,-59.));
#1136=CARTESIAN_POINT('',(0.463214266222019,-1.35978194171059,-59.));
#1137=CARTESIAN_POINT('',(0.427282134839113,-1.36152932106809,-59.));
#1138=B_SPLINE_CURVE_WITH_KNOTS('',3,(#1127,#1128,#1129,#1130,#1131,#1132,#1133,#1134,#1135,
#1136,#1137),.UNSPECIFIED.,.F.,.F.,(4,1,1,1,1,1,1,1,4),(0.,0.159004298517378,0.304646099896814,
0.438546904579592,0.562322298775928,0.677432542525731,0.786897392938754,0.893610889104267,1.),.UNSPECIFIED.);
#1139=DIRECTION('',(0.,0.,-1.));
#1140=VECTOR('',#1139,1.);
#1141=SURFACE_OF_LINEAR_EXTRUSION('',#1138,#1140);
#1142=ORIENTED_EDGE('',*,*,#107,.F.);
#1143=ORIENTED_EDGE('',*,*,#1122,.F.);
#1144=CARTESIAN_POINT('',(0.427282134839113,-1.36152932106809,-59.));
#1145=VERTEX_POINT('',#1144);
#1146=EDGE_CURVE('E208',#1115,#1145,#1138,.T.);
#1147=ORIENTED_EDGE('',*,*,#1146,.T.);
#1148=DIRECTION('',(0.,0.,-1.));
#1149=VECTOR('',#1148,1.);
#1150=CARTESIAN_POINT('',(0.427282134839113,-1.36152932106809,-59.));
#1151=LINE('',#1150,#1149);
#1152=EDGE_CURVE('E225',#1145,#106,#1151,.T.);
#1153=ORIENTED_EDGE('',*,*,#1152,.T.);
#1154=EDGE_LOOP('',(#1142,#1143,#1147,#1153));
#1155=FACE_BOUND('',#1154,.T.);
#1156=ADVANCED_FACE('F488',(#1155),#1141,.T.);
#1157=CARTESIAN_POINT('',(0.427282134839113,-1.36152932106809,-59.));
#1158=CARTESIAN_POINT('',(0.39659527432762,-1.36067464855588,-59.));
#1159=CARTESIAN_POINT('',(0.335758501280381,-1.35898025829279,-59.));
#1160=CARTESIAN_POINT('',(0.246196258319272,-1.34269945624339,-59.));
#1161=CARTESIAN_POINT('',(0.159214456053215,-1.31768732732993,-59.));
#1162=CARTESIAN_POINT('',(0.0766058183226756,-1.28186639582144,-59.));
#1163=CARTESIAN_POINT('',(-0.000489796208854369,-1.23852791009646,-59.));
#1164=CARTESIAN_POINT('',(-0.0680964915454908,-1.18618173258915,-59.));
#1165=CARTESIAN_POINT('',(-0.126542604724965,-1.12757552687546,-59.));
#1166=CARTESIAN_POINT('',(-0.174351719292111,-1.06219287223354,-59.));
#1167=CARTESIAN_POINT('',(-0.211031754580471,-0.991875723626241,-59.));
#1168=CARTESIAN_POINT('',(-0.239223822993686,-0.919699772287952,-59.));
#1169=CARTESIAN_POINT('',(-0.25486889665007,-0.844531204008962,-59.));
#1170=CARTESIAN_POINT('',(-0.257225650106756,-0.793920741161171,-59.));
#1171=CARTESIAN_POINT('',(-0.258414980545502,-0.768380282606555,-59.));
#1172=B_SPLINE_CURVE_WITH_KNOTS('',3,(#1157,#1158,#1159,#1160,#1161,#1162,#1163,#1164,#1165,
#1166,#1167,#1168,#1169,#1170,#1171),.UNSPECIFIED.,.F.,.F.,(4,1,1,1,1,1,1,1,1,1,1,1,4),(0.,
0.0912636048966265,0.180930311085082,0.270088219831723,0.360156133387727,0.448342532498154,
0.53266584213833,0.613833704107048,0.693981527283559,0.772715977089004,0.849335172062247,
0.923967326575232,1.),.UNSPECIFIED.);
#1173=DIRECTION('',(0.,0.,-1.));
#1174=VECTOR('',#1173,1.);
#1175=SURFACE_OF_LINEAR_EXTRUSION('',#1172,#1174);
#1176=ORIENTED_EDGE('',*,*,#127,.F.);
#1177=ORIENTED_EDGE('',*,*,#1152,.F.);
#1178=CARTESIAN_POINT('',(-0.258414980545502,-0.768380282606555,-59.));
#1179=VERTEX_POINT('',#1178);
#1180=EDGE_CURVE('E900',#1145,#1179,#1172,.T.);
#1181=ORIENTED_EDGE('',*,*,#1180,.T.);
#1182=DIRECTION('',(0.,0.,-1.));
#1183=VECTOR('',#1182,1.);
#1184=CARTESIAN_POINT('',(-0.258414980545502,-0.768380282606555,-59.));
#1185=LINE('',#1184,#1183);
#1186=EDGE_CURVE('E812',#1179,#126,#1185,.T.);
#1187=ORIENTED_EDGE('',*,*,#1186,.T.);
#1188=EDGE_LOOP('',(#1176,#1177,#1181,#1187));
#1189=FACE_BOUND('',#1188,.T.);
#1190=ADVANCED_FACE('F497',(#1189),#1175,.T.);
#1191=CARTESIAN_POINT('',(-0.258414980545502,-0.768380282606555,-59.));
#1192=CARTESIAN_POINT('',(-0.256940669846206,-0.739239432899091,-59.));
#1193=CARTESIAN_POINT('',(-0.253943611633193,-0.680000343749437,-59.));
#1194=CARTESIAN_POINT('',(-0.228612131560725,-0.592600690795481,-59.));
#1195=CARTESIAN_POINT('',(-0.188762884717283,-0.506108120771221,-59.));
#1196=CARTESIAN_POINT('',(-0.152000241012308,-0.45260685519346,-59.));
#1197=CARTESIAN_POINT('',(-0.132914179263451,-0.424830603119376,-59.));
#1198=B_SPLINE_CURVE_WITH_KNOTS('',3,(#1191,#1192,#1193,#1194,#1195,#1196,#1197),.UNSPECIFIED.,
.F.,.F.,(4,1,1,1,4),(0.,0.234723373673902,0.477158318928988,0.728556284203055,1.),.UNSPECIFIED.);
#1199=DIRECTION('',(0.,0.,-1.));
#1200=VECTOR('',#1199,1.);
#1201=SURFACE_OF_LINEAR_EXTRUSION('',#1198,#1200);
#1202=ORIENTED_EDGE('',*,*,#139,.F.);
#1203=ORIENTED_EDGE('',*,*,#1186,.F.);
#1204=CARTESIAN_POINT('',(-0.132914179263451,-0.424830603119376,-59.));
#1205=VERTEX_POINT('',#1204);
#1206=EDGE_CURVE('E891',#1179,#1205,#1198,.T.);
#1207=ORIENTED_EDGE('',*,*,#1206,.T.);
#1208=DIRECTION('',(0.,0.,-1.));
#1209=VECTOR('',#1208,1.);
#1210=CARTESIAN_POINT('',(-0.132914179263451,-0.424830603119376,-59.));
#1211=LINE('',#1210,#1209);
#1212=EDGE_CURVE('E810',#1205,#138,#1211,.T.);
#1213=ORIENTED_EDGE('',*,*,#1212,.T.);
#1214=EDGE_LOOP('',(#1202,#1203,#1207,#1213));
#1215=FACE_BOUND('',#1214,.T.);
#1216=ADVANCED_FACE('F507',(#1215),#1201,.T.);
#1217=CARTESIAN_POINT('',(-0.132914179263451,-0.424830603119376,-59.));
#1218=CARTESIAN_POINT('',(-0.117243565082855,-0.404783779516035,-59.));
#1219=CARTESIAN_POINT('',(-0.0843450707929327,-0.36269798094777,-59.));
#1220=CARTESIAN_POINT('',(-0.0277875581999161,-0.300052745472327,-59.));
#1221=CARTESIAN_POINT('',(0.0385785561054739,-0.235434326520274,-59.));
#1222=CARTESIAN_POINT('',(0.112482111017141,-0.166375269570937,-59.));
#1223=CARTESIAN_POINT('',(0.196615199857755,-0.0960874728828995,-59.));
#1224=CARTESIAN_POINT('',(0.288342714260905,-0.0212191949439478,-59.));
#1225=CARTESIAN_POINT('',(0.390006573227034,0.0553823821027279,-59.));
#1226=CARTESIAN_POINT('',(0.461306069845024,0.106754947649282,-59.));
#1227=CARTESIAN_POINT('',(0.498095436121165,0.133262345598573,-59.));
#1228=B_SPLINE_CURVE_WITH_KNOTS('',3,(#1217,#1218,#1219,#1220,#1221,#1222,#1223,#1224,#1225,
#1226,#1227),.UNSPECIFIED.,.F.,.F.,(4,1,1,1,1,1,1,1,4),(0.,0.0902792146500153,0.189529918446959,
0.299197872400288,0.418925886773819,0.548376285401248,0.688136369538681,0.83908350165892,1.),.UNSPECIFIED.);
#1229=DIRECTION('',(0.,0.,-1.));
#1230=VECTOR('',#1229,1.);
#1231=SURFACE_OF_LINEAR_EXTRUSION('',#1228,#1230);
#1232=ORIENTED_EDGE('',*,*,#155,.F.);
#1233=ORIENTED_EDGE('',*,*,#1212,.F.);
#1234=CARTESIAN_POINT('',(0.498095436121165,0.133262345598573,-59.));
#1235=VERTEX_POINT('',#1234);
#1236=EDGE_CURVE('E883',#1205,#1235,#1228,.T.);
#1237=ORIENTED_EDGE('',*,*,#1236,.T.);
#1238=DIRECTION('',(0.,0.,-1.));
#1239=VECTOR('',#1238,1.);
#1240=CARTESIAN_POINT('',(0.498095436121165,0.133262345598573,-59.));
#1241=LINE('',#1240,#1239);
#1242=EDGE_CURVE('E808',#1235,#154,#1241,.T.);
#1243=ORIENTED_EDGE('',*,*,#1242,.T.);
#1244=EDGE_LOOP('',(#1232,#1233,#1237,#1243));
#1245=FACE_BOUND('',#1244,.T.);
#1246=ADVANCED_FACE('F517',(#1245),#1231,.T.);
#1247=CARTESIAN_POINT('',(0.498095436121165,0.133262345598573,-59.));
#1248=CARTESIAN_POINT('',(0.534919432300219,0.1594909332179,-59.));
#1249=CARTESIAN_POINT('',(0.605324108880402,0.209637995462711,-59.));
#1250=CARTESIAN_POINT('',(0.703782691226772,0.284062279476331,-59.));
#1251=CARTESIAN_POINT('',(0.791827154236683,0.352106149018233,-59.));
#1252=CARTESIAN_POINT('',(0.869066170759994,0.414410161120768,-59.));
#1253=CARTESIAN_POINT('',(0.935465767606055,0.470982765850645,-59.));
#1254=CARTESIAN_POINT('',(0.9915491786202,0.521280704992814,-59.));
#1255=CARTESIAN_POINT('',(1.03588773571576,0.566664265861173,-59.));
#1256=CARTESIAN_POINT('',(1.06054331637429,0.596105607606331,-59.));
#1257=CARTESIAN_POINT('',(1.07161306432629,0.609324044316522,-59.));
#1258=B_SPLINE_CURVE_WITH_KNOTS('',3,(#1247,#1248,#1249,#1250,#1251,#1252,#1253,#1254,#1255,
#1256,#1257),.UNSPECIFIED.,.F.,.F.,(4,1,1,1,1,1,1,1,4),(0.,0.181535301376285,0.347081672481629,
0.495567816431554,0.628357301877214,0.745519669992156,0.845830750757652,0.930781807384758,1.),.UNSPECIFIED.);
#1259=DIRECTION('',(0.,0.,-1.));
#1260=VECTOR('',#1259,1.);
#1261=SURFACE_OF_LINEAR_EXTRUSION('',#1258,#1260);
#1262=ORIENTED_EDGE('',*,*,#171,.F.);
#1263=ORIENTED_EDGE('',*,*,#1242,.F.);
#1264=CARTESIAN_POINT('',(1.07161306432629,0.609324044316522,-59.));
#1265=VERTEX_POINT('',#1264);
#1266=EDGE_CURVE('E875',#1235,#1265,#1258,.T.);
#1267=ORIENTED_EDGE('',*,*,#1266,.T.);
#1268=DIRECTION('',(0.,0.,-1.));
#1269=VECTOR('',#1268,1.);
#1270=CARTESIAN_POINT('',(1.07161306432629,0.609324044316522,-59.));
#1271=LINE('',#1270,#1269);
#1272=EDGE_CURVE('E806',#1265,#170,#1271,.T.);
#1273=ORIENTED_EDGE('',*,*,#1272,.T.);
#1274=EDGE_LOOP('',(#1262,#1263,#1267,#1273));
#1275=FACE_BOUND('',#1274,.T.);
#1276=ADVANCED_FACE('F527',(#1275),#1261,.T.);
#1277=CARTESIAN_POINT('',(1.07161306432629,0.609324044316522,-59.));
#1278=CARTESIAN_POINT('',(1.08708560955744,0.629925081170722,-59.));
#1279=CARTESIAN_POINT('',(1.11751444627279,0.670439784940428,-59.));
#1280=CARTESIAN_POINT('',(1.15768045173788,0.733764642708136,-59.));
#1281=CARTESIAN_POINT('',(1.19181961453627,0.798587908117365,-59.));
#1282=CARTESIAN_POINT('',(1.21858194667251,0.865083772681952,-59.));
#1283=CARTESIAN_POINT('',(1.24111816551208,0.932318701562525,-59.));
#1284=CARTESIAN_POINT('',(1.25627609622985,1.00116994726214,-59.));
#1285=CARTESIAN_POINT('',(1.26576749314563,1.07132856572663,-59.));
#1286=CARTESIAN_POINT('',(1.26673947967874,1.11854206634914,-59.));
#1287=CARTESIAN_POINT('',(1.26722604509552,1.14217660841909,-59.));
#1288=B_SPLINE_CURVE_WITH_KNOTS('',3,(#1277,#1278,#1279,#1280,#1281,#1282,#1283,#1284,#1285,
#1286,#1287),.UNSPECIFIED.,.F.,.F.,(4,1,1,1,1,1,1,1,4),(0.,0.133506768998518,0.26255897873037,
0.388264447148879,0.512667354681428,0.63372226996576,0.755393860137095,0.877552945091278,1.),.UNSPECIFIED.);
#1289=DIRECTION('',(0.,0.,-1.));
#1290=VECTOR('',#1289,1.);
#1291=SURFACE_OF_LINEAR_EXTRUSION('',#1288,#1290);
#1292=ORIENTED_EDGE('',*,*,#187,.F.);
#1293=ORIENTED_EDGE('',*,*,#1272,.F.);
#1294=CARTESIAN_POINT('',(1.26722604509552,1.14217660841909,-59.));
#1295=VERTEX_POINT('',#1294);
#1296=EDGE_CURVE('E871',#1265,#1295,#1288,.T.);
#1297=ORIENTED_EDGE('',*,*,#1296,.T.);
#1298=DIRECTION('',(0.,0.,-1.));
#1299=VECTOR('',#1298,1.);
#1300=CARTESIAN_POINT('',(1.26722604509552,1.14217660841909,-59.));
#1301=LINE('',#1300,#1299);
#1302=EDGE_CURVE('E804',#1295,#186,#1301,.T.);
#1303=ORIENTED_EDGE('',*,*,#1302,.T.);
#1304=EDGE_LOOP('',(#1292,#1293,#1297,#1303));
#1305=FACE_BOUND('',#1304,.T.);
#1306=ADVANCED_FACE('F537',(#1305),#1291,.T.);
#1307=CARTESIAN_POINT('',(1.26722604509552,1.14217660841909,-59.));
#1308=CARTESIAN_POINT('',(1.26592083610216,1.17920638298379,-59.));
#1309=CARTESIAN_POINT('',(1.26333831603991,1.25247444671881,-59.));
#1310=CARTESIAN_POINT('',(1.2414977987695,1.35950527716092,-59.));
#1311=CARTESIAN_POINT('',(1.20702490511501,1.46169169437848,-59.));
#1312=CARTESIAN_POINT('',(1.15873001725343,1.5580220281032,-59.));
#1313=CARTESIAN_POINT('',(1.0964726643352,1.64598800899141,-59.));
#1314=CARTESIAN_POINT('',(1.02442668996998,1.72660149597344,-59.));
#1315=CARTESIAN_POINT('',(0.938615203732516,1.79437007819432,-59.));
#1316=CARTESIAN_POINT('',(0.844462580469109,1.85358213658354,-59.));
#1317=CARTESIAN_POINT('',(0.741406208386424,1.89992806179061,-59.));
#1318=CARTESIAN_POINT('',(0.633415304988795,1.9348890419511,-59.));
#1319=CARTESIAN_POINT('',(0.520318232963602,1.95469829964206,-59.));
#1320=CARTESIAN_POINT('',(0.443715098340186,1.9575410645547,-59.));
#1321=CARTESIAN_POINT('',(0.404846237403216,1.95898349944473,-59.));
#1322=B_SPLINE_CURVE_WITH_KNOTS('',3,(#1307,#1308,#1309,#1310,#1311,#1312,#1313,#1314,#1315,
#1316,#1317,#1318,#1319,#1320,#1321),.UNSPECIFIED.,.F.,.F.,(4,1,1,1,1,1,1,1,1,1,1,1,4),(0.,
0.0837853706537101,0.165779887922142,0.246280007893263,0.32746092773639,0.408796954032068,
0.489715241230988,0.571376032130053,0.655523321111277,0.741019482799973,0.826546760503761,
0.911988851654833,1.),.UNSPECIFIED.);
#1323=DIRECTION('',(0.,0.,-1.));
#1324=VECTOR('',#1323,1.);
#1325=SURFACE_OF_LINEAR_EXTRUSION('',#1322,#1324);
#1326=ORIENTED_EDGE('',*,*,#207,.F.);
#1327=ORIENTED_EDGE('',*,*,#1302,.F.);
#1328=CARTESIAN_POINT('',(0.404846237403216,1.95898349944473,-59.));
#1329=VERTEX_POINT('',#1328);
#1330=EDGE_CURVE('E862',#1295,#1329,#1322,.T.);
#1331=ORIENTED_EDGE('',*,*,#1330,.T.);
#1332=DIRECTION('',(0.,0.,-1.));
#1333=VECTOR('',#1332,1.);
#1334=CARTESIAN_POINT('',(0.404846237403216,1.95898349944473,-59.));
#1335=LINE('',#1334,#1333);
#1336=EDGE_CURVE('E802',#1329,#206,#1335,.T.);
#1337=ORIENTED_EDGE('',*,*,#1336,.T.);
#1338=EDGE_LOOP('',(#1326,#1327,#1331,#1337));
#1339=FACE_BOUND('',#1338,.T.);
#1340=ADVANCED_FACE('F547',(#1339),#1325,.T.);
#1341=CARTESIAN_POINT('',(0.404846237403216,1.95898349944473,-59.));
#1342=CARTESIAN_POINT('',(0.363602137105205,1.95756094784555,-59.));
#1343=CARTESIAN_POINT('',(0.281580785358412,1.95473194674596,-59.));
#1344=CARTESIAN_POINT('',(0.160931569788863,1.93013441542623,-59.));
#1345=CARTESIAN_POINT('',(0.0447708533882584,1.88943374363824,-59.));
#1346=CARTESIAN_POINT('',(-0.048672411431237,1.84324508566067,-59.));
#1347=CARTESIAN_POINT('',(-0.121805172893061,1.7971136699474,-59.));
#1348=CARTESIAN_POINT('',(-0.177577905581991,1.75509384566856,-59.));
#1349=CARTESIAN_POINT('',(-0.234095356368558,1.70671873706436,-59.));
#1350=CARTESIAN_POINT('',(-0.291813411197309,1.65185949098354,-59.));
#1351=CARTESIAN_POINT('',(-0.349754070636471,1.59001273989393,-59.));
#1352=CARTESIAN_POINT('',(-0.408777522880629,1.52160205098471,-59.));
#1353=CARTESIAN_POINT('',(-0.46902179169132,1.44704549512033,-59.));
#1354=CARTESIAN_POINT('',(-0.507777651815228,1.39382099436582,-59.));
#1355=CARTESIAN_POINT('',(-0.527645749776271,1.36653558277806,-59.));
#1356=B_SPLINE_CURVE_WITH_KNOTS('',3,(#1341,#1342,#1343,#1344,#1345,#1346,#1347,#1348,#1349,
#1350,#1351,#1352,#1353,#1354,#1355),.UNSPECIFIED.,.F.,.F.,(4,1,1,1,1,1,1,1,1,1,1,1,4),(0.,
0.107232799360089,0.213251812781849,0.318830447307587,0.426793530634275,0.483645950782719,
0.543603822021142,0.608307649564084,0.677126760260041,0.750685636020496,0.828713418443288,
0.912190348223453,1.),.UNSPECIFIED.);
#1357=DIRECTION('',(0.,0.,-1.));
#1358=VECTOR('',#1357,1.);
#1359=SURFACE_OF_LINEAR_EXTRUSION('',#1356,#1358);
#1360=ORIENTED_EDGE('',*,*,#227,.F.);
#1361=ORIENTED_EDGE('',*,*,#1336,.F.);
#1362=CARTESIAN_POINT('',(-0.527645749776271,1.36653558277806,-59.));
#1363=VERTEX_POINT('',#1362);
#1364=EDGE_CURVE('E857',#1329,#1363,#1356,.T.);
#1365=ORIENTED_EDGE('',*,*,#1364,.T.);
#1366=DIRECTION('',(0.,0.,-1.));
#1367=VECTOR('',#1366,1.);
#1368=CARTESIAN_POINT('',(-0.527645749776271,1.36653558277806,-59.));
#1369=LINE('',#1368,#1367);
#1370=EDGE_CURVE('E800',#1363,#226,#1369,.T.);
#1371=ORIENTED_EDGE('',*,*,#1370,.T.);
#1372=EDGE_LOOP('',(#1360,#1361,#1365,#1371));
#1373=FACE_BOUND('',#1372,.T.);
#1374=ADVANCED_FACE('F557',(#1373),#1359,.T.);
#1375=CARTESIAN_POINT('',(-0.527645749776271,1.36653558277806,-59.));
#1376=DIRECTION('',(0.604084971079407,0.796919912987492,0.));
#1377=DIRECTION('',(-0.796919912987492,0.604084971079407,0.));
#1378=AXIS2_PLACEMENT_3D('',#1375,#1376,#1377);
#1379=PLANE('',#1378);
#1380=ORIENTED_EDGE('',*,*,#235,.F.);
#1381=ORIENTED_EDGE('',*,*,#1370,.F.);
#1382=DIRECTION('',(0.796919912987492,-0.604084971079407,0.));
#1383=VECTOR('',#1382,1.);
#1384=CARTESIAN_POINT('',(-0.527645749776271,1.36653558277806,-59.));
#1385=LINE('',#1384,#1383);
#1386=CARTESIAN_POINT('',(-0.243691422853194,1.15129119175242,-59.));
#1387=VERTEX_POINT('',#1386);
#1388=EDGE_CURVE('E852',#1363,#1387,#1385,.T.);
#1389=ORIENTED_EDGE('',*,*,#1388,.T.);
#1390=DIRECTION('',(0.,0.,-1.));
#1391=VECTOR('',#1390,1.);
#1392=CARTESIAN_POINT('',(-0.243691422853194,1.15129119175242,-59.));
#1393=LINE('',#1392,#1391);
#1394=EDGE_CURVE('E798',#1387,#234,#1393,.T.);
#1395=ORIENTED_EDGE('',*,*,#1394,.T.);
#1396=EDGE_LOOP('',(#1380,#1381,#1389,#1395));
#1397=FACE_BOUND('',#1396,.T.);
#1398=ADVANCED_FACE('F567',(#1397),#1379,.T.);
#1399=CARTESIAN_POINT('',(-0.243691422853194,1.15129119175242,-59.));
#1400=CARTESIAN_POINT('',(-0.226545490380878,1.17337988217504,-59.));
#1401=CARTESIAN_POINT('',(-0.193526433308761,1.21591753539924,-59.));
#1402=CARTESIAN_POINT('',(-0.143396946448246,1.2754888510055,-59.));
#1403=CARTESIAN_POINT('',(-0.0961482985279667,1.32990533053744,-59.));
#1404=CARTESIAN_POINT('',(-0.049597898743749,1.37717045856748,-59.));
#1405=CARTESIAN_POINT('',(-0.00620426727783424,1.41987259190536,-59.));
#1406=CARTESIAN_POINT('',(0.0359127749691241,1.45643234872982,-59.));
#1407=CARTESIAN_POINT('',(0.0761471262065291,1.48720794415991,-59.));
#1408=CARTESIAN_POINT('',(0.126864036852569,1.52005150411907,-59.));
#1409=CARTESIAN_POINT('',(0.190581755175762,1.55260800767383,-59.));
#1410=CARTESIAN_POINT('',(0.27056629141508,1.58015708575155,-59.));
#1411=CARTESIAN_POINT('',(0.354152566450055,1.59671214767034,-59.));
#1412=CARTESIAN_POINT('',(0.411082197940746,1.59890103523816,-59.));
#1413=CARTESIAN_POINT('',(0.439902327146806,1.60000914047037,-59.));
#1414=B_SPLINE_CURVE_WITH_KNOTS('',3,(#1399,#1400,#1401,#1402,#1403,#1404,#1405,#1406,#1407,
#1408,#1409,#1410,#1411,#1412,#1413),.UNSPECIFIED.,.F.,.F.,(4,1,1,1,1,1,1,1,1,1,1,1,4),(0.,
0.0984694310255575,0.189629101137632,0.27418408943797,0.352183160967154,0.42319887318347,
0.488550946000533,0.548473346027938,0.601440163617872,0.701198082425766,0.799591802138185,
0.898545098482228,1.),.UNSPECIFIED.);
#1415=DIRECTION('',(0.,0.,-1.));
#1416=VECTOR('',#1415,1.);
#1417=SURFACE_OF_LINEAR_EXTRUSION('',#1414,#1416);
#1418=ORIENTED_EDGE('',*,*,#255,.F.);
#1419=ORIENTED_EDGE('',*,*,#1394,.F.);
#1420=CARTESIAN_POINT('',(0.439902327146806,1.60000914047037,-59.));
#1421=VERTEX_POINT('',#1420);
#1422=EDGE_CURVE('E844',#1387,#1421,#1414,.T.);
#1423=ORIENTED_EDGE('',*,*,#1422,.T.);
#1424=DIRECTION('',(0.,0.,-1.));
#1425=VECTOR('',#1424,1.);
#1426=CARTESIAN_POINT('',(0.439902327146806,1.60000914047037,-59.));
#1427=LINE('',#1426,#1425);
#1428=EDGE_CURVE('E796',#1421,#254,#1427,.T.);
#1429=ORIENTED_EDGE('',*,*,#1428,.T.);
#1430=EDGE_LOOP('',(#1418,#1419,#1423,#1429));
#1431=FACE_BOUND('',#1430,.T.);
#1432=ADVANCED_FACE('F577',(#1431),#1417,.T.);
#1433=CARTESIAN_POINT('',(0.439902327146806,1.60000914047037,-59.));
#1434=CARTESIAN_POINT('',(0.476058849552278,1.59879744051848,-59.));
#1435=CARTESIAN_POINT('',(0.545783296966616,1.59646079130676,-59.));
#1436=CARTESIAN_POINT('',(0.644773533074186,1.57094080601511,-59.));
#1437=CARTESIAN_POINT('',(0.733867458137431,1.53075894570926,-59.));
#1438=CARTESIAN_POINT('',(0.810420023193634,1.47444396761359,-59.));
#1439=CARTESIAN_POINT('',(0.874157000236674,1.40772297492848,-59.));
#1440=CARTESIAN_POINT('',(0.920262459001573,1.33094411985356,-59.));
#1441=CARTESIAN_POINT('',(0.94801262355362,1.24616171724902,-59.));
#1442=CARTESIAN_POINT('',(0.951398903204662,1.18702006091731,-59.));
#1443=CARTESIAN_POINT('',(0.95312348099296,1.15690016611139,-59.));
#1444=B_SPLINE_CURVE_WITH_KNOTS('',3,(#1433,#1434,#1435,#1436,#1437,#1438,#1439,#1440,#1441,
#1442,#1443),.UNSPECIFIED.,.F.,.F.,(4,1,1,1,1,1,1,1,4),(0.,0.143073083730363,0.27590296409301,
0.402370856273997,0.528413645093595,0.650356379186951,0.765895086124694,0.880774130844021,1.),.UNSPECIFIED.);
#1445=DIRECTION('',(0.,0.,-1.));
#1446=VECTOR('',#1445,1.);
#1447=SURFACE_OF_LINEAR_EXTRUSION('',#1444,#1446);
#1448=ORIENTED_EDGE('',*,*,#271,.F.);
#1449=ORIENTED_EDGE('',*,*,#1428,.F.);
#1450=CARTESIAN_POINT('',(0.95312348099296,1.15690016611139,-59.));
#1451=VERTEX_POINT('',#1450);
#1452=EDGE_CURVE('E828',#1421,#1451,#1444,.T.);
#1453=ORIENTED_EDGE('',*,*,#1452,.T.);
#1454=DIRECTION('',(0.,0.,-1.));
#1455=VECTOR('',#1454,1.);
#1456=CARTESIAN_POINT('',(0.95312348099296,1.15690016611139,-59.));
#1457=LINE('',#1456,#1455);
#1458=EDGE_CURVE('E794',#1451,#270,#1457,.T.);
#1459=ORIENTED_EDGE('',*,*,#1458,.T.);
#1460=EDGE_LOOP('',(#1448,#1449,#1453,#1459));
#1461=FACE_BOUND('',#1460,.T.);
#1462=ADVANCED_FACE('F587',(#1461),#1447,.T.);
#1463=CARTESIAN_POINT('',(0.95312348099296,1.15690016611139,-59.));
#1464=CARTESIAN_POINT('',(0.952730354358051,1.13814868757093,-59.));
#1465=CARTESIAN_POINT('',(0.951943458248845,1.10061506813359,-59.));
#1466=CARTESIAN_POINT('',(0.94096866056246,1.04516364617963,-59.));
#1467=CARTESIAN_POINT('',(0.92686933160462,0.989852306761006,-59.));
#1468=CARTESIAN_POINT('',(0.904526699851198,0.934929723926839,-59.));
#1469=CARTESIAN_POINT('',(0.873681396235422,0.879435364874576,-59.));
#1470=CARTESIAN_POINT('',(0.833176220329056,0.822413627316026,-59.));
#1471=CARTESIAN_POINT('',(0.782162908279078,0.763361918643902,-59.));
#1472=CARTESIAN_POINT('',(0.74308589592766,0.724954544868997,-59.));
#1473=CARTESIAN_POINT('',(0.722454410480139,0.704676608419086,-59.));
#1474=B_SPLINE_CURVE_WITH_KNOTS('',3,(#1463,#1464,#1465,#1466,#1467,#1468,#1469,#1470,#1471,
#1472,#1473),.UNSPECIFIED.,.F.,.F.,(4,1,1,1,1,1,1,1,4),(0.,0.107285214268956,0.21474586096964,
0.322938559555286,0.434116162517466,0.553412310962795,0.68607298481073,0.834255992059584,1.),.UNSPECIFIED.);
#1475=DIRECTION('',(0.,0.,-1.));
#1476=VECTOR('',#1475,1.);
#1477=SURFACE_OF_LINEAR_EXTRUSION('',#1474,#1476);
#1478=ORIENTED_EDGE('',*,*,#287,.F.);
#1479=ORIENTED_EDGE('',*,*,#1458,.F.);
#1480=CARTESIAN_POINT('',(0.722454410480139,0.704676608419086,-59.));
#1481=VERTEX_POINT('',#1480);
#1482=EDGE_CURVE('E826',#1451,#1481,#1474,.T.);
#1483=ORIENTED_EDGE('',*,*,#1482,.T.);
#1484=DIRECTION('',(0.,0.,-1.));
#1485=VECTOR('',#1484,1.);
#1486=CARTESIAN_POINT('',(0.722454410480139,0.704676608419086,-59.));
#1487=LINE('',#1486,#1485);
#1488=EDGE_CURVE('E792',#1481,#286,#1487,.T.);
#1489=ORIENTED_EDGE('',*,*,#1488,.T.);
#1490=EDGE_LOOP('',(#1478,#1479,#1483,#1489));
#1491=FACE_BOUND('',#1490,.T.);
#1492=ADVANCED_FACE('F597',(#1491),#1477,.T.);
#1493=CARTESIAN_POINT('',(0.722454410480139,0.704676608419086,-59.));
#1494=CARTESIAN_POINT('',(0.71479303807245,0.697839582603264,-59.));
#1495=CARTESIAN_POINT('',(0.696591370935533,0.681596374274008,-59.));
#1496=CARTESIAN_POINT('',(0.663315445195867,0.655004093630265,-59.));
#1497=CARTESIAN_POINT('',(0.619372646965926,0.622201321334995,-59.));
#1498=CARTESIAN_POINT('',(0.565910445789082,0.581614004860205,-59.));
#1499=CARTESIAN_POINT('',(0.501943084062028,0.534532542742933,-59.));
#1500=CARTESIAN_POINT('',(0.42746352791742,0.481558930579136,-59.));
#1501=CARTESIAN_POINT('',(0.343301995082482,0.420973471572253,-59.));
#1502=CARTESIAN_POINT('',(0.283580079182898,0.378615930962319,-59.));
#1503=CARTESIAN_POINT('',(0.252001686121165,0.356219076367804,-59.));
#1504=B_SPLINE_CURVE_WITH_KNOTS('',3,(#1493,#1494,#1495,#1496,#1497,#1498,#1499,#1500,#1501,
#1502,#1503),.UNSPECIFIED.,.F.,.F.,(4,1,1,1,1,1,1,1,4),(0.,0.0525942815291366,0.124951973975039,
0.218093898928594,0.333502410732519,0.468789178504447,0.624937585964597,0.801683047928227,1.),.UNSPECIFIED.);
#1505=DIRECTION('',(0.,0.,-1.));
#1506=VECTOR('',#1505,1.);
#1507=SURFACE_OF_LINEAR_EXTRUSION('',#1504,#1506);
#1508=ORIENTED_EDGE('',*,*,#303,.F.);
#1509=ORIENTED_EDGE('',*,*,#1488,.F.);
#1510=CARTESIAN_POINT('',(0.252001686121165,0.356219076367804,-59.));
#1511=VERTEX_POINT('',#1510);
#1512=EDGE_CURVE('E824',#1481,#1511,#1504,.T.);
#1513=ORIENTED_EDGE('',*,*,#1512,.T.);
#1514=DIRECTION('',(0.,0.,-1.));
#1515=VECTOR('',#1514,1.);
#1516=CARTESIAN_POINT('',(0.252001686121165,0.356219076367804,-59.));
#1517=LINE('',#1516,#1515);
#1518=EDGE_CURVE('E790',#1511,#302,#1517,.T.);
#1519=ORIENTED_EDGE('',*,*,#1518,.T.);
#1520=EDGE_LOOP('',(#1508,#1509,#1513,#1519));
#1521=FACE_BOUND('',#1520,.T.);
#1522=ADVANCED_FACE('F607',(#1521),#1507,.T.);
#1523=CARTESIAN_POINT('',(0.252001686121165,0.356219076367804,-59.));
#1524=CARTESIAN_POINT('',(0.21401577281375,0.328577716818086,-59.));
#1525=CARTESIAN_POINT('',(0.140461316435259,0.275054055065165,-59.));
#1526=CARTESIAN_POINT('',(0.0358037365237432,0.194638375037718,-59.));
#1527=CARTESIAN_POINT('',(-0.0590900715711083,0.115990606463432,-59.));
#1528=CARTESIAN_POINT('',(-0.144553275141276,0.039612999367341,-59.));
#1529=CARTESIAN_POINT('',(-0.221430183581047,-0.0339150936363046,-59.));
#1530=CARTESIAN_POINT('',(-0.288867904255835,-0.105478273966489,-59.));
#1531=CARTESIAN_POINT('',(-0.347553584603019,-0.174563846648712,-59.));
#1532=CARTESIAN_POINT('',(-0.41073280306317,-0.263136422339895,-59.));
#1533=CARTESIAN_POINT('',(-0.475290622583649,-0.371917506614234,-59.));
#1534=CARTESIAN_POINT('',(-0.530732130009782,-0.505195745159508,-59.));
#1535=CARTESIAN_POINT('',(-0.565690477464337,-0.638992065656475,-59.));
#1536=CARTESIAN_POINT('',(-0.570261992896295,-0.728918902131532,-59.));
#1537=CARTESIAN_POINT('',(-0.572517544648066,-0.773288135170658,-59.));
#1538=B_SPLINE_CURVE_WITH_KNOTS('',3,(#1523,#1524,#1525,#1526,#1527,#1528,#1529,#1530,#1531,
#1532,#1533,#1534,#1535,#1536,#1537),.UNSPECIFIED.,.F.,.F.,(4,1,1,1,1,1,1,1,1,1,1,1,4),(0.,
0.0969723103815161,0.187773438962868,0.272396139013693,0.351320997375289,0.424334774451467,
0.491908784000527,0.554233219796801,0.611267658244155,0.716347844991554,0.814540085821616,
0.908495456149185,1.),.UNSPECIFIED.);
#1539=DIRECTION('',(0.,0.,-1.));
#1540=VECTOR('',#1539,1.);
#1541=SURFACE_OF_LINEAR_EXTRUSION('',#1538,#1540);
#1542=ORIENTED_EDGE('',*,*,#321,.F.);
#1543=ORIENTED_EDGE('',*,*,#1518,.F.);
#1544=CARTESIAN_POINT('',(-0.572517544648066,-0.773288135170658,-59.));
#1545=VERTEX_POINT('',#1544);
#1546=EDGE_CURVE('E658',#1511,#1545,#1538,.T.);
#1547=ORIENTED_EDGE('',*,*,#1546,.T.);
#1548=DIRECTION('',(0.,0.,-1.));
#1549=VECTOR('',#1548,1.);
#1550=CARTESIAN_POINT('',(-0.572517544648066,-0.773288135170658,-59.));
#1551=LINE('',#1550,#1549);
#1552=EDGE_CURVE('E788',#1545,#56,#1551,.T.);
#1553=ORIENTED_EDGE('',*,*,#1552,.T.);
#1554=EDGE_LOOP('',(#1542,#1543,#1547,#1553));
#1555=FACE_BOUND('',#1554,.T.);
#1556=ADVANCED_FACE('F617',(#1555),#1541,.T.);
#1557=CARTESIAN_POINT('',(-0.572517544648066,-0.773288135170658,-59.));
#1558=CARTESIAN_POINT('',(-0.571860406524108,-0.804666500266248,-59.));
#1559=CARTESIAN_POINT('',(-0.570558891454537,-0.866813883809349,-59.));
#1560=CARTESIAN_POINT('',(-0.555597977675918,-0.95806896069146,-59.));
#1561=CARTESIAN_POINT('',(-0.533678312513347,-1.04669983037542,-59.));
#1562=CARTESIAN_POINT('',(-0.500641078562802,-1.13161094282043,-59.));
#1563=CARTESIAN_POINT('',(-0.460317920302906,-1.21435570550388,-59.));
#1564=CARTESIAN_POINT('',(-0.409151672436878,-1.2927636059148,-59.));
#1565=CARTESIAN_POINT('',(-0.349843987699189,-1.36857000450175,-59.));
#1566=CARTESIAN_POINT('',(-0.281810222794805,-1.43975349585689,-59.));
#1567=CARTESIAN_POINT('',(-0.207364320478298,-1.5050996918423,-59.));
#1568=CARTESIAN_POINT('',(-0.128680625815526,-1.56322875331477,-59.));
#1569=CARTESIAN_POINT('',(-0.0456303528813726,-1.61169707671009,-59.));
#1570=CARTESIAN_POINT('',(0.0413359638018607,-1.65124791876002,-59.));
#1571=CARTESIAN_POINT('',(0.132238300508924,-1.68218143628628,-59.));
#1572=CARTESIAN_POINT('',(0.227046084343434,-1.70459430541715,-59.));
#1573=CARTESIAN_POINT('',(0.325915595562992,-1.71835001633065,-59.));
#1574=CARTESIAN_POINT('',(0.393116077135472,-1.71977777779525,-59.));
#1575=CARTESIAN_POINT('',(0.427282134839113,-1.72050368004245,-59.));
#1576=B_SPLINE_CURVE_WITH_KNOTS('',3,(#1557,#1558,#1559,#1560,#1561,#1562,#1563,#1564,#1565,
#1566,#1567,#1568,#1569,#1570,#1571,#1572,#1573,#1574,#1575),.UNSPECIFIED.,.F.,.F.,(4,1,1,1,1,1,
1,1,1,1,1,1,1,1,1,1,4),(0.,0.0614842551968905,0.12177452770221,0.180919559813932,
0.240256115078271,0.300114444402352,0.361145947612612,0.423500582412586,0.488669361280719,
0.553954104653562,0.617581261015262,0.68023842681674,0.742187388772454,0.804663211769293,
0.868258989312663,0.933020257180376,1.),.UNSPECIFIED.);
#1577=DIRECTION('',(0.,0.,-1.));
#1578=VECTOR('',#1577,1.);
#1579=SURFACE_OF_LINEAR_EXTRUSION('',#1576,#1578);
#1580=ORIENTED_EDGE('',*,*,#59,.F.);
#1581=ORIENTED_EDGE('',*,*,#1552,.F.);
#1582=EDGE_CURVE('E653',#1545,#1087,#1576,.T.);
#1583=ORIENTED_EDGE('',*,*,#1582,.T.);
#1584=ORIENTED_EDGE('',*,*,#1088,.T.);
#1585=EDGE_LOOP('',(#1580,#1581,#1583,#1584));
#1586=FACE_BOUND('',#1585,.T.);
#1587=ADVANCED_FACE('F627',(#1586),#1579,.T.);
#1588=CARTESIAN_POINT('',(1.07041680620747,-1.50006313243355,-59.));
#1589=DIRECTION('',(0.,-2.78349678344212E-12,-1.));
#1590=DIRECTION('',(0.,1.,-2.78349678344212E-12));
#1591=AXIS2_PLACEMENT_3D('',#1588,#1589,#1590);
#1592=PLANE('',#1591);
#1593=ORIENTED_EDGE('',*,*,#1092,.F.);
#1594=ORIENTED_EDGE('',*,*,#1582,.F.);
#1595=ORIENTED_EDGE('',*,*,#1546,.F.);
#1596=ORIENTED_EDGE('',*,*,#1512,.F.);
#1597=ORIENTED_EDGE('',*,*,#1482,.F.);
#1598=ORIENTED_EDGE('',*,*,#1452,.F.);
#1599=ORIENTED_EDGE('',*,*,#1422,.F.);
#1600=ORIENTED_EDGE('',*,*,#1388,.F.);
#1601=ORIENTED_EDGE('',*,*,#1364,.F.);
#1602=ORIENTED_EDGE('',*,*,#1330,.F.);
#1603=ORIENTED_EDGE('',*,*,#1296,.F.);
#1604=ORIENTED_EDGE('',*,*,#1266,.F.);
#1605=ORIENTED_EDGE('',*,*,#1236,.F.);
#1606=ORIENTED_EDGE('',*,*,#1206,.F.);
#1607=ORIENTED_EDGE('',*,*,#1180,.F.);
#1608=ORIENTED_EDGE('',*,*,#1146,.F.);
#1609=ORIENTED_EDGE('',*,*,#1116,.F.);
#1610=EDGE_LOOP('',(#1593,#1594,#1595,#1596,#1597,#1598,#1599,#1600,#1601,#1602,#1603,#1604,
#1605,#1606,#1607,#1608,#1609));
#1611=FACE_BOUND('',#1610,.T.);
#1612=ADVANCED_FACE('F204',(#1611),#1592,.T.);
#1613=CLOSED_SHELL('',(#325,#409,#429,#454,#629,#696,#711,#871,#951,#973,#987,#1001,#1013,#1037,
#1047,#1057,#1102,#1126,#1156,#1190,#1216,#1246,#1276,#1306,#1340,#1374,#1398,#1432,#1462,#1492,
#1522,#1556,#1587,#1612));
#1614=MANIFOLD_SOLID_BREP('B2',#1613);
#1615=ADVANCED_BREP_SHAPE_REPRESENTATION('',(#18,#1614),#14);
#1616=SHAPE_DEFINITION_REPRESENTATION(#9,#1615);
ENDSEC;
END-ISO-10303-21;
